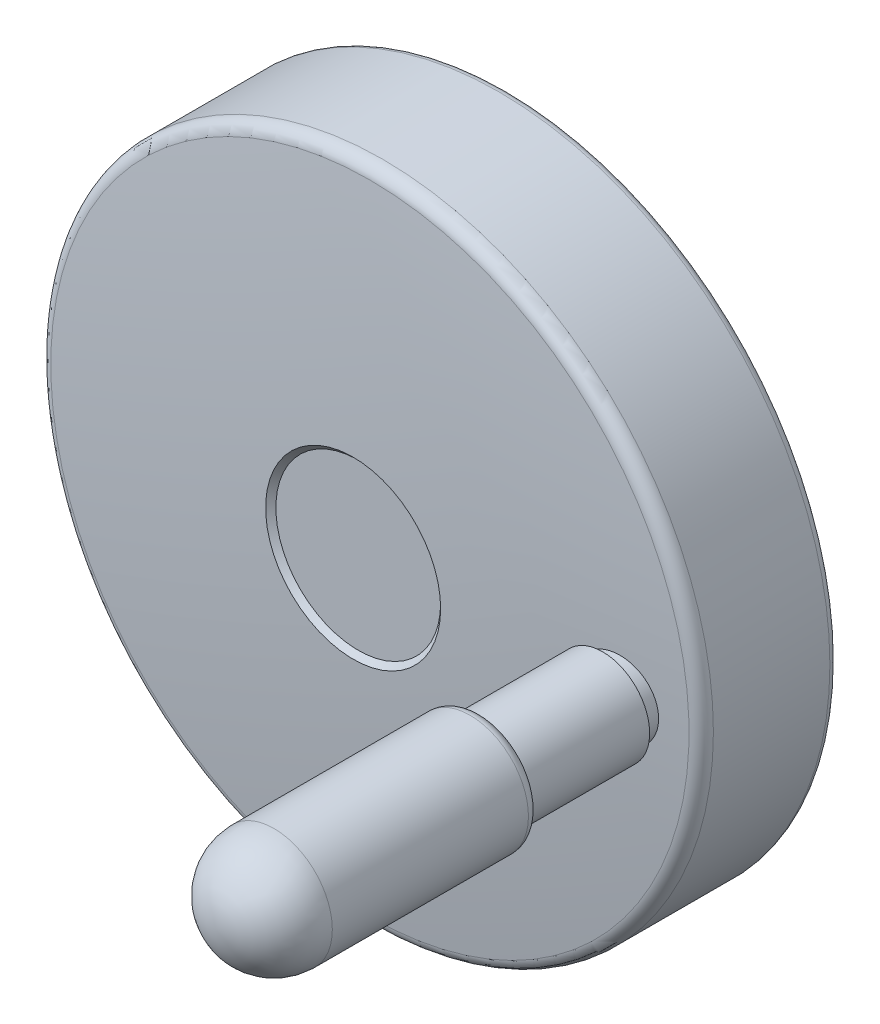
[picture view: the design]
ISO-10303-21;
HEADER;
FILE_DESCRIPTION(('STEP AP214'),'2;1');
FILE_NAME('part.step','',(''),(''),'','','');
FILE_SCHEMA(('AUTOMOTIVE_DESIGN { 1 0 10303 214 1 1 1 1 }'));
ENDSEC;
DATA;
#1=APPLICATION_CONTEXT('core data for automotive mechanical design processes');
#2=APPLICATION_PROTOCOL_DEFINITION('international standard','automotive_design',2000,#1);
#3=PRODUCT_CONTEXT('',#1,'mechanical');
#4=PRODUCT('Part','Part','',(#3));
#5=PRODUCT_RELATED_PRODUCT_CATEGORY('part','',(#4));
#6=PRODUCT_DEFINITION_FORMATION('','',#4);
#7=PRODUCT_DEFINITION_CONTEXT('part definition',#1,'design');
#8=PRODUCT_DEFINITION('design','',#6,#7);
#9=PRODUCT_DEFINITION_SHAPE('','',#8);
#10=(LENGTH_UNIT() NAMED_UNIT(*) SI_UNIT(.MILLI.,.METRE.));
#11=(NAMED_UNIT(*) PLANE_ANGLE_UNIT() SI_UNIT($,.RADIAN.));
#12=(NAMED_UNIT(*) SI_UNIT($,.STERADIAN.) SOLID_ANGLE_UNIT());
#13=UNCERTAINTY_MEASURE_WITH_UNIT(LENGTH_MEASURE(1.E-05),#10,'distance_accuracy_value','');
#14=(GEOMETRIC_REPRESENTATION_CONTEXT(3) GLOBAL_UNCERTAINTY_ASSIGNED_CONTEXT((#13)) GLOBAL_UNIT_ASSIGNED_CONTEXT((#10,
#11,#12)) REPRESENTATION_CONTEXT('',''));
#15=CARTESIAN_POINT('',(0.,0.,0.));
#16=DIRECTION('',(0.,0.,1.));
#17=DIRECTION('',(1.,0.,0.));
#18=AXIS2_PLACEMENT_3D('',#15,#16,#17);
#19=CARTESIAN_POINT('',(0.,0.,34.));
#20=DIRECTION('',(0.,0.,1.));
#21=DIRECTION('',(0.,1.,0.));
#22=AXIS2_PLACEMENT_3D('',#19,#20,#21);
#23=PLANE('',#22);
#24=CARTESIAN_POINT('',(39.,0.,34.));
#25=DIRECTION('',(0.,0.,1.));
#26=DIRECTION('',(0.,1.,0.));
#27=AXIS2_PLACEMENT_3D('',#24,#25,#26);
#28=CIRCLE('',#27,5.4375);
#29=CARTESIAN_POINT('',(39.,5.43749999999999,34.));
#30=VERTEX_POINT('',#29);
#31=EDGE_CURVE('E392',#30,#30,#28,.T.);
#32=ORIENTED_EDGE('',*,*,#31,.F.);
#33=EDGE_LOOP('',(#32));
#34=FACE_BOUND('',#33,.T.);
#35=CARTESIAN_POINT('',(39.,0.,34.));
#36=DIRECTION('',(0.,0.,-1.));
#37=DIRECTION('',(0.,-1.,0.));
#38=AXIS2_PLACEMENT_3D('',#35,#36,#37);
#39=CIRCLE('',#38,6.);
#40=CARTESIAN_POINT('',(39.,-6.,34.));
#41=VERTEX_POINT('',#40);
#42=EDGE_CURVE('E433',#41,#41,#39,.T.);
#43=ORIENTED_EDGE('',*,*,#42,.F.);
#44=EDGE_LOOP('',(#43));
#45=FACE_BOUND('',#44,.T.);
#46=ADVANCED_FACE('F15',(#34,#45),#23,.T.);
#47=CARTESIAN_POINT('',(39.,0.,31.));
#48=DIRECTION('',(0.,0.,-1.));
#49=DIRECTION('',(0.,-1.,0.));
#50=AXIS2_PLACEMENT_3D('',#47,#48,#49);
#51=CYLINDRICAL_SURFACE('',#50,6.);
#52=CARTESIAN_POINT('',(33.,0.,32.74646972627));
#53=CARTESIAN_POINT('',(33.0000009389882,0.167957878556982,32.746469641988));
#54=CARTESIAN_POINT('',(33.0070584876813,0.335946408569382,32.7458350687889));
#55=CARTESIAN_POINT('',(33.0352437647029,0.67076337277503,32.7433007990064));
#56=CARTESIAN_POINT('',(33.0563756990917,0.837591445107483,32.7414007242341));
#57=CARTESIAN_POINT('',(33.1126039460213,1.16913659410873,32.7363449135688));
#58=CARTESIAN_POINT('',(33.1477224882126,1.3338498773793,32.7331871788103));
#59=CARTESIAN_POINT('',(33.2317016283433,1.65984619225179,32.7256359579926));
#60=CARTESIAN_POINT('',(33.2805732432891,1.82112636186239,32.7212414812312));
#61=CARTESIAN_POINT('',(33.3915896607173,2.13868510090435,32.7112588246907));
#62=CARTESIAN_POINT('',(33.4537102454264,2.29497220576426,32.7056728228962));
#63=CARTESIAN_POINT('',(33.5908580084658,2.60181401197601,32.6933399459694));
#64=CARTESIAN_POINT('',(33.6658910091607,2.75236608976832,32.6865925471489));
#65=CARTESIAN_POINT('',(33.8283063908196,3.04660896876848,32.67198682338));
#66=CARTESIAN_POINT('',(33.9156894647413,3.19029938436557,32.6641284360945));
#67=CARTESIAN_POINT('',(34.1021303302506,3.4697365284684,32.6473612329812));
#68=CARTESIAN_POINT('',(34.2011828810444,3.60548678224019,32.6384528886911));
#69=CARTESIAN_POINT('',(34.4105368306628,3.868480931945,32.6196238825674));
#70=CARTESIAN_POINT('',(34.5208648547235,3.99570346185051,32.6097008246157));
#71=CARTESIAN_POINT('',(34.7516660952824,4.24027152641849,32.5889414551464));
#72=CARTESIAN_POINT('',(34.8721294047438,4.35762648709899,32.5781060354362));
#73=CARTESIAN_POINT('',(35.1224921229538,4.58183185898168,32.5555855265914));
#74=CARTESIAN_POINT('',(35.2523959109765,4.68867734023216,32.5439000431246));
#75=CARTESIAN_POINT('',(35.5206970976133,4.89108337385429,32.5197639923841));
#76=CARTESIAN_POINT('',(35.6590964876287,4.98664126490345,32.5073132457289));
#77=CARTESIAN_POINT('',(35.9438733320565,5.16609261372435,32.4816928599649));
#78=CARTESIAN_POINT('',(36.0902767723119,5.24994450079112,32.4685208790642));
#79=CARTESIAN_POINT('',(36.3896344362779,5.40503648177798,32.4415862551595));
#80=CARTESIAN_POINT('',(36.5425910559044,5.47627191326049,32.4278233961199));
#81=CARTESIAN_POINT('',(36.8538629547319,5.60557650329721,32.3998141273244));
#82=CARTESIAN_POINT('',(37.0121762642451,5.66365044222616,32.3855678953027));
#83=CARTESIAN_POINT('',(37.3331552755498,5.7662838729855,32.3566823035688));
#84=CARTESIAN_POINT('',(37.4958225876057,5.8108382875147,32.342042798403));
#85=CARTESIAN_POINT('',(37.8248270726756,5.88621612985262,32.3124319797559));
#86=CARTESIAN_POINT('',(37.9911742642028,5.9169954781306,32.2974597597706));
#87=CARTESIAN_POINT('',(38.3259327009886,5.96441315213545,32.2673279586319));
#88=CARTESIAN_POINT('',(38.4943448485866,5.98104505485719,32.2521682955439));
#89=CARTESIAN_POINT('',(38.8319675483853,6.00002939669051,32.2217754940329));
#90=CARTESIAN_POINT('',(39.00117811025,6.00238166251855,32.2065423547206));
#91=CARTESIAN_POINT('',(39.3391201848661,5.99279224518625,32.1761175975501));
#92=CARTESIAN_POINT('',(39.5078518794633,5.9808570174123,32.1609259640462));
#93=CARTESIAN_POINT('',(39.8440908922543,5.94274356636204,32.1306513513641));
#94=CARTESIAN_POINT('',(40.0115946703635,5.91653385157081,32.1155686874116));
#95=CARTESIAN_POINT('',(40.343743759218,5.85004512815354,32.0856592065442));
#96=CARTESIAN_POINT('',(40.5083901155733,5.80977138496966,32.0708322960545));
#97=CARTESIAN_POINT('',(40.833778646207,5.7154144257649,32.0415285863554));
#98=CARTESIAN_POINT('',(40.9945192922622,5.66132589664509,32.0270519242));
#99=CARTESIAN_POINT('',(41.3108232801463,5.53974661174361,31.9985634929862));
#100=CARTESIAN_POINT('',(41.4663885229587,5.47226084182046,31.9845515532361));
#101=CARTESIAN_POINT('',(41.7712243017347,5.3243780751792,31.9570933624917));
#102=CARTESIAN_POINT('',(41.9204975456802,5.24398670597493,31.9436468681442));
#103=CARTESIAN_POINT('',(42.2117156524,5.07085509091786,31.9174128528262));
#104=CARTESIAN_POINT('',(42.3536622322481,4.97811775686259,31.9046251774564));
#105=CARTESIAN_POINT('',(42.6291782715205,4.7809774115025,31.8798034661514));
#106=CARTESIAN_POINT('',(42.7627516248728,4.67657988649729,31.8677690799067));
#107=CARTESIAN_POINT('',(43.0207558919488,4.45671145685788,31.8445230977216));
#108=CARTESIAN_POINT('',(43.1451777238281,4.34122980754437,31.833312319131));
#109=CARTESIAN_POINT('',(43.3833915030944,4.10054176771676,31.8118477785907));
#110=CARTESIAN_POINT('',(43.497220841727,3.97537268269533,31.8015906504));
#111=CARTESIAN_POINT('',(43.7139888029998,3.71576617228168,31.7820571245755));
#112=CARTESIAN_POINT('',(43.8169224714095,3.58132457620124,31.7727811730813));
#113=CARTESIAN_POINT('',(44.0110846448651,3.30418746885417,31.7552835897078));
#114=CARTESIAN_POINT('',(44.1023139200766,3.1614925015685,31.7470618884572));
#115=CARTESIAN_POINT('',(44.2723701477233,2.86892460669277,31.7317358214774));
#116=CARTESIAN_POINT('',(44.3512027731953,2.71905500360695,31.7246309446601));
#117=CARTESIAN_POINT('',(44.495778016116,2.41348899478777,31.7116006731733));
#118=CARTESIAN_POINT('',(44.5615493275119,2.25780627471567,31.7056726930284));
#119=CARTESIAN_POINT('',(44.6796916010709,1.94153919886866,31.6950243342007));
#120=CARTESIAN_POINT('',(44.7320733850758,1.78095891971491,31.6903029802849));
#121=CARTESIAN_POINT('',(44.8230489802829,1.4561921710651,31.6821029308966));
#122=CARTESIAN_POINT('',(44.8616649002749,1.29201193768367,31.6786222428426));
#123=CARTESIAN_POINT('',(44.924935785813,0.960995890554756,31.6729192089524));
#124=CARTESIAN_POINT('',(44.9495949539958,0.794160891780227,31.6706964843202));
#125=CARTESIAN_POINT('',(44.9781180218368,0.522551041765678,31.6681254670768));
#126=CARTESIAN_POINT('',(44.9863211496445,0.418216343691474,31.6673860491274));
#127=CARTESIAN_POINT('',(44.9972624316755,0.209258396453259,31.6663998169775));
#128=CARTESIAN_POINT('',(45.000000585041,0.104635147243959,31.6661530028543));
#129=CARTESIAN_POINT('',(44.999999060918,-0.167955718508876,31.6661531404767));
#130=CARTESIAN_POINT('',(44.9929416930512,-0.335942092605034,31.6667892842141));
#131=CARTESIAN_POINT('',(44.9647571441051,-0.670754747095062,31.6693297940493));
#132=CARTESIAN_POINT('',(44.9436257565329,-0.837580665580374,31.6712345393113));
#133=CARTESIAN_POINT('',(44.8873989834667,-1.16912152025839,31.6763026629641));
#134=CARTESIAN_POINT('',(44.8522813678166,-1.33383266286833,31.6794680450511));
#135=CARTESIAN_POINT('',(44.7683044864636,-1.65982470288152,31.6870373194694));
#136=CARTESIAN_POINT('',(44.7194342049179,-1.82110273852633,31.6914422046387));
#137=CARTESIAN_POINT('',(44.6084209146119,-2.13865716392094,31.7014481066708));
#138=CARTESIAN_POINT('',(44.5463021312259,-2.29494209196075,31.7070469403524));
#139=CARTESIAN_POINT('',(44.4091584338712,-2.60177964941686,31.7194075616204));
#140=CARTESIAN_POINT('',(44.3341276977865,-2.75232965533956,31.7261698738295));
#141=CARTESIAN_POINT('',(44.1717173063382,-3.04656858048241,31.7408070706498));
#142=CARTESIAN_POINT('',(44.0843369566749,-3.19025711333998,31.7486820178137));
#143=CARTESIAN_POINT('',(43.8979019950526,-3.46969074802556,31.7654835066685));
#144=CARTESIAN_POINT('',(43.7988526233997,-3.60543937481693,31.7744095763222));
#145=CARTESIAN_POINT('',(43.5895042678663,-3.86843211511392,31.7932748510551));
#146=CARTESIAN_POINT('',(43.4791785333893,-3.99565476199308,31.8032164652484));
#147=CARTESIAN_POINT('',(43.2483820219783,-4.24022325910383,31.8240130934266));
#148=CARTESIAN_POINT('',(43.127921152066,-4.3575785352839,31.8348672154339));
#149=CARTESIAN_POINT('',(42.8775634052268,-4.58178480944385,31.8574247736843));
#150=CARTESIAN_POINT('',(42.7476621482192,-4.68863087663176,31.8691286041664));
#151=CARTESIAN_POINT('',(42.4793660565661,-4.89103839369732,31.8933004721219));
#152=CARTESIAN_POINT('',(42.3409692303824,-4.98659718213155,31.9057686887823));
#153=CARTESIAN_POINT('',(42.0561950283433,-5.16605221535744,31.9314229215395));
#154=CARTESIAN_POINT('',(41.9097915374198,-5.24990668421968,31.9446112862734));
#155=CARTESIAN_POINT('',(41.6104334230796,-5.40500375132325,31.9715768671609));
#156=CARTESIAN_POINT('',(41.457476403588,-5.47624168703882,31.9853542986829));
#157=CARTESIAN_POINT('',(41.1462033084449,-5.6055511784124,32.0133904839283));
#158=CARTESIAN_POINT('',(40.9878892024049,-5.66362751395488,32.0276490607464));
#159=CARTESIAN_POINT('',(40.6669081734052,-5.76626558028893,32.0565567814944));
#160=CARTESIAN_POINT('',(40.5042396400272,-5.81082223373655,32.0712060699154));
#161=CARTESIAN_POINT('',(40.175231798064,-5.88620444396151,32.1008336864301));
#162=CARTESIAN_POINT('',(40.0088824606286,-5.91698588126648,32.1158129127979));
#163=CARTESIAN_POINT('',(39.6741192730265,-5.96440735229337,32.1459556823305));
#164=CARTESIAN_POINT('',(39.505704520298,-5.98104096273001,32.1611193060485));
#165=CARTESIAN_POINT('',(39.1680761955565,-6.00002825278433,32.1915168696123));
#166=CARTESIAN_POINT('',(38.9988626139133,-6.00238175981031,32.2067508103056));
#167=CARTESIAN_POINT('',(38.6609141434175,-5.99279427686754,32.2371739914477));
#168=CARTESIAN_POINT('',(38.4921790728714,-5.98085974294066,32.2523632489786));
#169=CARTESIAN_POINT('',(38.1559354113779,-5.94274733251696,32.2826297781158));
#170=CARTESIAN_POINT('',(37.9884303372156,-5.91653816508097,32.2977067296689));
#171=CARTESIAN_POINT('',(37.656278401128,-5.85005025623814,32.3276018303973));
#172=CARTESIAN_POINT('',(37.4916304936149,-5.80977678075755,32.3424200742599));
#173=CARTESIAN_POINT('',(37.1662386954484,-5.71542003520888,32.3717037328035));
#174=CARTESIAN_POINT('',(37.0054963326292,-5.66133145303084,32.3861690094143));
#175=CARTESIAN_POINT('',(36.6891888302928,-5.53975171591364,32.414632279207));
#176=CARTESIAN_POINT('',(36.5336217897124,-5.47226554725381,32.4286304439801));
#177=CARTESIAN_POINT('',(36.2287851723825,-5.32438296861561,32.4560588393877));
#178=CARTESIAN_POINT('',(36.0795127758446,-5.24399241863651,32.4694893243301));
#179=CARTESIAN_POINT('',(35.7882961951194,-5.07086255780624,32.4956897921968));
#180=CARTESIAN_POINT('',(35.6463502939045,-4.97812615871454,32.5084599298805));
#181=CARTESIAN_POINT('',(35.3708354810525,-4.78098781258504,32.5332455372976));
#182=CARTESIAN_POINT('',(35.2372626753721,-4.67659135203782,32.5452613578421));
#183=CARTESIAN_POINT('',(34.9792593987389,-4.45672520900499,32.5684696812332));
#184=CARTESIAN_POINT('',(34.8548380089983,-4.34124478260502,32.5796613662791));
#185=CARTESIAN_POINT('',(34.6166255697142,-4.10055993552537,32.6010877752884));
#186=CARTESIAN_POINT('',(34.5027970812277,-3.97539286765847,32.6113258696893));
#187=CARTESIAN_POINT('',(34.2860305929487,-3.7157906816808,32.6308219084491));
#188=CARTESIAN_POINT('',(34.1830975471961,-3.58135139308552,32.6400794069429));
#189=CARTESIAN_POINT('',(33.9889363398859,-3.30421917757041,32.6575412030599));
#190=CARTESIAN_POINT('',(33.8977074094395,-3.1615267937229,32.6657455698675));
#191=CARTESIAN_POINT('',(33.7276515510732,-2.86896433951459,32.6810385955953));
#192=CARTESIAN_POINT('',(33.6488189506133,-2.71909759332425,32.6881277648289));
#193=CARTESIAN_POINT('',(33.504242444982,-2.41353555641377,32.7011288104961));
#194=CARTESIAN_POINT('',(33.4384700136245,-2.25785387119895,32.7070432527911));
#195=CARTESIAN_POINT('',(33.3203254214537,-1.94158894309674,32.7176669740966));
#196=CARTESIAN_POINT('',(33.2679424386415,-1.78100977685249,32.7223772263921));
#197=CARTESIAN_POINT('',(33.1769643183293,-1.45624526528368,32.7305578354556));
#198=CARTESIAN_POINT('',(33.1383470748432,-1.2920661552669,32.7340301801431));
#199=CARTESIAN_POINT('',(33.0750733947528,-0.961052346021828,32.7397195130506));
#200=CARTESIAN_POINT('',(33.050412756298,-0.794218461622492,32.7419368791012));
#201=CARTESIAN_POINT('',(33.0218860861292,-0.522600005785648,32.7445018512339));
#202=CARTESIAN_POINT('',(33.0136814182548,-0.418255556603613,32.7452395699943));
#203=CARTESIAN_POINT('',(33.0027380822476,-0.209278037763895,32.7462235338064));
#204=CARTESIAN_POINT('',(32.99999941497,-0.10464496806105,32.7464697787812));
#205=CARTESIAN_POINT('',(33.,0.,32.74646972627));
#206=B_SPLINE_CURVE_WITH_KNOTS('',3,(#52,#53,#54,#55,#56,#57,#58,#59,#60,#61,#62,#63,#64,#65,
#66,#67,#68,#69,#70,#71,#72,#73,#74,#75,#76,#77,#78,#79,#80,#81,#82,#83,#84,#85,#86,#87,#88,#89,
#90,#91,#92,#93,#94,#95,#96,#97,#98,#99,#100,#101,#102,#103,#104,#105,#106,#107,#108,#109,#110,
#111,#112,#113,#114,#115,#116,#117,#118,#119,#120,#121,#122,#123,#124,#125,#126,#127,#128,#129,
#130,#131,#132,#133,#134,#135,#136,#137,#138,#139,#140,#141,#142,#143,#144,#145,#146,#147,#148,
#149,#150,#151,#152,#153,#154,#155,#156,#157,#158,#159,#160,#161,#162,#163,#164,#165,#166,#167,
#168,#169,#170,#171,#172,#173,#174,#175,#176,#177,#178,#179,#180,#181,#182,#183,#184,#185,#186,
#187,#188,#189,#190,#191,#192,#193,#194,#195,#196,#197,#198,#199,#200,#201,#202,#203,#204,#205),
.UNSPECIFIED.,.T.,.F.,(4,2,2,2,2,2,2,2,2,2,2,2,2,2,2,2,2,2,2,2,2,2,2,2,2,2,2,2,2,2,2,2,2,2,2,2,
2,2,2,2,2,2,2,2,2,2,2,2,2,2,2,2,2,2,2,2,2,2,2,2,2,2,2,2,2,2,2,2,2,2,2,2,2,2,2,2,4),(0.,
0.503777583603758,1.00770578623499,1.51243812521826,2.01757594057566,2.52179820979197,
3.02624843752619,3.53072698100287,4.03497981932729,4.54045215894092,5.04543602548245,
5.55065565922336,6.05599417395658,6.56308393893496,7.07036071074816,7.57745293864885,
8.0847353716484,8.59362967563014,9.10275489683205,9.61188629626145,10.1207877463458,
10.6308164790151,11.1406544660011,11.6506888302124,12.1605337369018,12.6701569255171,
13.1796601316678,13.6889246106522,14.1986878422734,14.7065773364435,15.2146967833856,
15.722782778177,16.2306355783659,16.7373600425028,17.2436736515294,17.7491703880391,
18.2545148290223,18.5683603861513,18.8822059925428,19.3859771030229,19.8898988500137,
20.3946247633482,20.8997561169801,21.4039716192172,21.908415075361,22.4128869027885,
22.9171330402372,23.4226044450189,23.9275873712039,24.4328061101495,24.9381437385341,
25.4452412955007,25.9525258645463,26.4596259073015,26.9669161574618,27.4758197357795,
27.9849542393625,28.494094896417,29.0030055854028,29.5130363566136,30.0228763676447,
30.5329127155,31.0427595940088,31.5523755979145,32.0618716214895,32.5711289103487,
33.08088491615,33.5887647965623,34.0968746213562,34.6049510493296,35.1127943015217,
35.619515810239,36.1258264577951,36.6313203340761,37.1366619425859,37.450536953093,
37.7644120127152),.UNSPECIFIED.);
#207=CARTESIAN_POINT('',(33.,0.,32.74646972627));
#208=VERTEX_POINT('',#207);
#209=EDGE_CURVE('E396',#208,#208,#206,.T.);
#210=ORIENTED_EDGE('',*,*,#209,.F.);
#211=EDGE_LOOP('',(#210));
#212=FACE_BOUND('',#211,.T.);
#213=ORIENTED_EDGE('',*,*,#42,.T.);
#214=EDGE_LOOP('',(#213));
#215=FACE_BOUND('',#214,.T.);
#216=ADVANCED_FACE('F407',(#212,#215),#51,.T.);
#217=CARTESIAN_POINT('',(2.81085775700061E-13,0.,-401.000000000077));
#218=DIRECTION('',(-1.,0.,0.));
#219=DIRECTION('',(0.,0.,1.));
#220=AXIS2_PLACEMENT_3D('',#217,#218,#219);
#221=SPHERICAL_SURFACE('',#220,435.000000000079);
#222=CARTESIAN_POINT('',(0.,0.,31.2057017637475));
#223=DIRECTION('',(0.,0.,1.));
#224=DIRECTION('',(0.,1.,0.));
#225=AXIS2_PLACEMENT_3D('',#222,#223,#224);
#226=CIRCLE('',#225,49.2263279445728);
#227=CARTESIAN_POINT('',(0.,49.2263279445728,31.2057017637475));
#228=VERTEX_POINT('',#227);
#229=EDGE_CURVE('E389',#228,#228,#226,.T.);
#230=ORIENTED_EDGE('',*,*,#229,.T.);
#231=EDGE_LOOP('',(#230));
#232=FACE_BOUND('',#231,.T.);
#233=CARTESIAN_POINT('',(0.,0.,33.7904667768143));
#234=DIRECTION('',(0.,0.,1.));
#235=DIRECTION('',(1.,0.,0.));
#236=AXIS2_PLACEMENT_3D('',#233,#234,#235);
#237=CIRCLE('',#236,13.5);
#238=CARTESIAN_POINT('',(13.5,0.,33.7904667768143));
#239=VERTEX_POINT('',#238);
#240=EDGE_CURVE('E393',#239,#239,#237,.F.);
#241=ORIENTED_EDGE('',*,*,#240,.T.);
#242=EDGE_LOOP('',(#241));
#243=FACE_BOUND('',#242,.T.);
#244=ORIENTED_EDGE('',*,*,#209,.T.);
#245=EDGE_LOOP('',(#244));
#246=FACE_BOUND('',#245,.T.);
#247=ADVANCED_FACE('F411',(#232,#243,#246),#221,.T.);
#248=CARTESIAN_POINT('',(0.,0.,29.21854911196));
#249=DIRECTION('',(0.,0.,1.));
#250=DIRECTION('',(0.,1.,0.));
#251=AXIS2_PLACEMENT_3D('',#248,#249,#250);
#252=TOROIDAL_SURFACE('',#251,49.,2.00000000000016);
#253=CARTESIAN_POINT('',(0.,0.,29.21854911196));
#254=DIRECTION('',(0.,0.,1.));
#255=DIRECTION('',(0.,1.,0.));
#256=AXIS2_PLACEMENT_3D('',#253,#254,#255);
#257=CIRCLE('',#256,51.);
#258=CARTESIAN_POINT('',(0.,51.,29.21854911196));
#259=VERTEX_POINT('',#258);
#260=EDGE_CURVE('E404',#259,#259,#257,.T.);
#261=ORIENTED_EDGE('',*,*,#260,.T.);
#262=EDGE_LOOP('',(#261));
#263=FACE_BOUND('',#262,.T.);
#264=ORIENTED_EDGE('',*,*,#229,.F.);
#265=EDGE_LOOP('',(#264));
#266=FACE_BOUND('',#265,.T.);
#267=ADVANCED_FACE('F417',(#263,#266),#252,.T.);
#268=CARTESIAN_POINT('',(0.,0.,33.7904667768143));
#269=DIRECTION('',(0.,0.,1.));
#270=DIRECTION('',(1.,0.,0.));
#271=AXIS2_PLACEMENT_3D('',#268,#269,#270);
#272=CONICAL_SURFACE('',#271,13.5,0.78539816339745);
#273=CARTESIAN_POINT('',(0.,0.,33.));
#274=DIRECTION('',(0.,0.,1.));
#275=DIRECTION('',(1.,0.,0.));
#276=AXIS2_PLACEMENT_3D('',#273,#274,#275);
#277=CIRCLE('',#276,12.7095332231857);
#278=CARTESIAN_POINT('',(12.7095332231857,0.,33.));
#279=VERTEX_POINT('',#278);
#280=EDGE_CURVE('E405',#279,#279,#277,.T.);
#281=ORIENTED_EDGE('',*,*,#280,.F.);
#282=EDGE_LOOP('',(#281));
#283=FACE_BOUND('',#282,.T.);
#284=ORIENTED_EDGE('',*,*,#240,.F.);
#285=EDGE_LOOP('',(#284));
#286=FACE_BOUND('',#285,.T.);
#287=ADVANCED_FACE('F859',(#283,#286),#272,.F.);
#288=CARTESIAN_POINT('',(0.,0.,20.2342745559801));
#289=DIRECTION('',(0.,0.,-1.));
#290=DIRECTION('',(-1.,0.,0.));
#291=AXIS2_PLACEMENT_3D('',#288,#289,#290);
#292=CYLINDRICAL_SURFACE('',#291,51.);
#293=CARTESIAN_POINT('',(0.,0.,11.25));
#294=DIRECTION('',(0.,0.,-1.));
#295=DIRECTION('',(-1.,0.,0.));
#296=AXIS2_PLACEMENT_3D('',#293,#294,#295);
#297=CIRCLE('',#296,51.);
#298=CARTESIAN_POINT('',(-51.,0.,11.25));
#299=VERTEX_POINT('',#298);
#300=EDGE_CURVE('E273',#299,#299,#297,.F.);
#301=ORIENTED_EDGE('',*,*,#300,.T.);
#302=EDGE_LOOP('',(#301));
#303=FACE_BOUND('',#302,.T.);
#304=ORIENTED_EDGE('',*,*,#260,.F.);
#305=EDGE_LOOP('',(#304));
#306=FACE_BOUND('',#305,.T.);
#307=ADVANCED_FACE('F867',(#303,#306),#292,.T.);
#308=CARTESIAN_POINT('',(-6.35476661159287,0.,33.));
#309=DIRECTION('',(0.,0.,1.));
#310=DIRECTION('',(0.,1.,0.));
#311=AXIS2_PLACEMENT_3D('',#308,#309,#310);
#312=PLANE('',#311);
#313=ORIENTED_EDGE('',*,*,#280,.T.);
#314=EDGE_LOOP('',(#313));
#315=FACE_BOUND('',#314,.T.);
#316=ADVANCED_FACE('F262',(#315),#312,.T.);
#317=CARTESIAN_POINT('',(0.,0.,11.25));
#318=DIRECTION('',(0.,0.,1.));
#319=DIRECTION('',(0.,1.,0.));
#320=AXIS2_PLACEMENT_3D('',#317,#318,#319);
#321=TOROIDAL_SURFACE('',#320,49.75,1.25);
#322=ORIENTED_EDGE('',*,*,#300,.F.);
#323=EDGE_LOOP('',(#322));
#324=FACE_BOUND('',#323,.T.);
#325=CARTESIAN_POINT('',(0.,0.,10.));
#326=DIRECTION('',(0.,0.,1.));
#327=DIRECTION('',(0.,-1.,0.));
#328=AXIS2_PLACEMENT_3D('',#325,#326,#327);
#329=CIRCLE('',#328,49.75);
#330=CARTESIAN_POINT('',(0.,-49.75,10.));
#331=VERTEX_POINT('',#330);
#332=CARTESIAN_POINT('',(0.,49.75,10.));
#333=VERTEX_POINT('',#332);
#334=EDGE_CURVE('E304',#331,#333,#329,.T.);
#335=ORIENTED_EDGE('',*,*,#334,.T.);
#336=CARTESIAN_POINT('',(0.,0.,10.));
#337=DIRECTION('',(0.,0.,1.));
#338=DIRECTION('',(0.,1.,0.));
#339=AXIS2_PLACEMENT_3D('',#336,#337,#338);
#340=CIRCLE('',#339,49.75);
#341=CARTESIAN_POINT('',(-49.75,0.,10.));
#342=VERTEX_POINT('',#341);
#343=EDGE_CURVE('E245',#333,#342,#340,.T.);
#344=ORIENTED_EDGE('',*,*,#343,.T.);
#345=CARTESIAN_POINT('',(0.,0.,10.));
#346=DIRECTION('',(0.,0.,1.));
#347=DIRECTION('',(-1.,0.,0.));
#348=AXIS2_PLACEMENT_3D('',#345,#346,#347);
#349=CIRCLE('',#348,49.75);
#350=EDGE_CURVE('E38',#342,#331,#349,.T.);
#351=ORIENTED_EDGE('',*,*,#350,.T.);
#352=EDGE_LOOP('',(#335,#344,#351));
#353=FACE_BOUND('',#352,.T.);
#354=ADVANCED_FACE('F250',(#324,#353),#321,.T.);
#355=CARTESIAN_POINT('',(-49.355,0.,10.));
#356=DIRECTION('',(0.,0.,-1.));
#357=DIRECTION('',(-1.,0.,0.));
#358=AXIS2_PLACEMENT_3D('',#355,#356,#357);
#359=PLANE('',#358);
#360=CARTESIAN_POINT('',(0.,0.,10.));
#361=DIRECTION('',(0.,0.,-1.));
#362=DIRECTION('',(-1.,0.,0.));
#363=AXIS2_PLACEMENT_3D('',#360,#361,#362);
#364=CIRCLE('',#363,48.96);
#365=CARTESIAN_POINT('',(-48.96,0.,9.99999999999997));
#366=VERTEX_POINT('',#365);
#367=EDGE_CURVE('E324',#366,#366,#364,.F.);
#368=ORIENTED_EDGE('',*,*,#367,.T.);
#369=EDGE_LOOP('',(#368));
#370=FACE_BOUND('',#369,.T.);
#371=ORIENTED_EDGE('',*,*,#343,.F.);
#372=ORIENTED_EDGE('',*,*,#334,.F.);
#373=ORIENTED_EDGE('',*,*,#350,.F.);
#374=EDGE_LOOP('',(#371,#372,#373));
#375=FACE_BOUND('',#374,.T.);
#376=ADVANCED_FACE('F261',(#370,#375),#359,.T.);
#377=CARTESIAN_POINT('',(0.,0.,11.8));
#378=DIRECTION('',(0.,0.,-1.));
#379=DIRECTION('',(-1.,0.,0.));
#380=AXIS2_PLACEMENT_3D('',#377,#378,#379);
#381=CYLINDRICAL_SURFACE('',#380,48.96);
#382=ORIENTED_EDGE('',*,*,#367,.F.);
#383=EDGE_LOOP('',(#382));
#384=FACE_BOUND('',#383,.T.);
#385=CARTESIAN_POINT('',(0.,0.,13.6));
#386=DIRECTION('',(0.,0.,-1.));
#387=DIRECTION('',(-1.,0.,0.));
#388=AXIS2_PLACEMENT_3D('',#385,#386,#387);
#389=CIRCLE('',#388,48.96);
#390=CARTESIAN_POINT('',(-48.96,0.,13.6));
#391=VERTEX_POINT('',#390);
#392=EDGE_CURVE('E328',#391,#391,#389,.T.);
#393=ORIENTED_EDGE('',*,*,#392,.F.);
#394=EDGE_LOOP('',(#393));
#395=FACE_BOUND('',#394,.T.);
#396=ADVANCED_FACE('F289',(#384,#395),#381,.F.);
#397=CARTESIAN_POINT('',(39.,0.,25.5));
#398=DIRECTION('',(0.,0.,1.));
#399=DIRECTION('',(0.,1.,0.));
#400=AXIS2_PLACEMENT_3D('',#397,#398,#399);
#401=CYLINDRICAL_SURFACE('',#400,2.4585);
#402=CARTESIAN_POINT('',(39.,0.,21.0719999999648));
#403=DIRECTION('',(0.,0.,1.));
#404=DIRECTION('',(0.,1.,0.));
#405=AXIS2_PLACEMENT_3D('',#402,#403,#404);
#406=CIRCLE('',#405,2.4585);
#407=CARTESIAN_POINT('',(39.,2.45849999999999,21.0719999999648));
#408=VERTEX_POINT('',#407);
#409=EDGE_CURVE('E30',#408,#408,#406,.T.);
#410=ORIENTED_EDGE('',*,*,#409,.T.);
#411=EDGE_LOOP('',(#410));
#412=FACE_BOUND('',#411,.T.);
#413=CARTESIAN_POINT('',(39.,0.,17.5415));
#414=DIRECTION('',(0.,0.,1.));
#415=DIRECTION('',(0.,1.,0.));
#416=AXIS2_PLACEMENT_3D('',#413,#414,#415);
#417=CIRCLE('',#416,2.4585);
#418=CARTESIAN_POINT('',(39.,2.4585,17.5415));
#419=VERTEX_POINT('',#418);
#420=EDGE_CURVE('E325',#419,#419,#417,.T.);
#421=ORIENTED_EDGE('',*,*,#420,.F.);
#422=EDGE_LOOP('',(#421));
#423=FACE_BOUND('',#422,.T.);
#424=ADVANCED_FACE('F504',(#412,#423),#401,.F.);
#425=CARTESIAN_POINT('',(39.,0.,17.0000000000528));
#426=DIRECTION('',(0.,0.,-1.));
#427=DIRECTION('',(0.,-1.,0.));
#428=AXIS2_PLACEMENT_3D('',#425,#426,#427);
#429=CONICAL_SURFACE('',#428,2.99999999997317,0.785398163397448);
#430=ORIENTED_EDGE('',*,*,#420,.T.);
#431=EDGE_LOOP('',(#430));
#432=FACE_BOUND('',#431,.T.);
#433=CARTESIAN_POINT('',(39.,0.,16.9999999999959));
#434=DIRECTION('',(0.,0.,-1.));
#435=DIRECTION('',(0.,-1.,0.));
#436=AXIS2_PLACEMENT_3D('',#433,#434,#435);
#437=CIRCLE('',#436,3.00000000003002);
#438=CARTESIAN_POINT('',(39.,-3.00000000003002,16.9999999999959));
#439=VERTEX_POINT('',#438);
#440=EDGE_CURVE('E331',#439,#439,#437,.F.);
#441=ORIENTED_EDGE('',*,*,#440,.F.);
#442=EDGE_LOOP('',(#441));
#443=FACE_BOUND('',#442,.T.);
#444=ADVANCED_FACE('F497',(#432,#443),#429,.F.);
#445=CARTESIAN_POINT('',(42.3,0.,17.));
#446=DIRECTION('',(0.,0.,1.));
#447=DIRECTION('',(0.,1.,0.));
#448=AXIS2_PLACEMENT_3D('',#445,#446,#447);
#449=PLANE('',#448);
#450=ORIENTED_EDGE('',*,*,#440,.T.);
#451=EDGE_LOOP('',(#450));
#452=FACE_BOUND('',#451,.T.);
#453=CARTESIAN_POINT('',(39.,0.,17.));
#454=DIRECTION('',(0.,0.,1.));
#455=DIRECTION('',(0.,1.,0.));
#456=AXIS2_PLACEMENT_3D('',#453,#454,#455);
#457=CIRCLE('',#456,3.6);
#458=CARTESIAN_POINT('',(39.,3.6,17.));
#459=VERTEX_POINT('',#458);
#460=EDGE_CURVE('E335',#459,#459,#457,.T.);
#461=ORIENTED_EDGE('',*,*,#460,.F.);
#462=EDGE_LOOP('',(#461));
#463=FACE_BOUND('',#462,.T.);
#464=ADVANCED_FACE('F493',(#452,#463),#449,.F.);
#465=CARTESIAN_POINT('',(39.,0.,8.5));
#466=DIRECTION('',(0.,0.,1.));
#467=DIRECTION('',(0.,1.,0.));
#468=AXIS2_PLACEMENT_3D('',#465,#466,#467);
#469=CYLINDRICAL_SURFACE('',#468,3.6);
#470=CARTESIAN_POINT('',(35.6551589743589,-1.33117936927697,13.6));
#471=CARTESIAN_POINT('',(35.6298127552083,-1.26750935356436,13.6277047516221));
#472=CARTESIAN_POINT('',(35.6060345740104,-1.2024530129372,13.6537276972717));
#473=CARTESIAN_POINT('',(35.5619033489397,-1.06975467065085,13.7020707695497));
#474=CARTESIAN_POINT('',(35.5415545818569,-1.00210956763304,13.7243862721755));
#475=CARTESIAN_POINT('',(35.5046580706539,-0.8646634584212,13.7648801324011));
#476=CARTESIAN_POINT('',(35.488105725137,-0.794865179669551,13.7830634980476));
#477=CARTESIAN_POINT('',(35.4590718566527,-0.653477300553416,13.8149769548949));
#478=CARTESIAN_POINT('',(35.4465875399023,-0.581888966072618,13.8287101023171));
#479=CARTESIAN_POINT('',(35.4242827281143,-0.425901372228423,13.853255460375));
#480=CARTESIAN_POINT('',(35.4151960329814,-0.341266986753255,13.8632619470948));
#481=CARTESIAN_POINT('',(35.4030565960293,-0.171085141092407,13.8766320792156));
#482=CARTESIAN_POINT('',(35.4000006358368,-0.0855381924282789,13.879999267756));
#483=CARTESIAN_POINT('',(35.3999994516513,0.0737685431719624,13.8800006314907));
#484=CARTESIAN_POINT('',(35.4022712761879,0.147530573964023,13.8774974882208));
#485=CARTESIAN_POINT('',(35.411308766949,0.294474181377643,13.8675430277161));
#486=CARTESIAN_POINT('',(35.4180762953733,0.367655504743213,13.8600896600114));
#487=CARTESIAN_POINT('',(35.4359822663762,0.512981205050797,13.840379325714));
#488=CARTESIAN_POINT('',(35.4471299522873,0.585123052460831,13.8281122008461));
#489=CARTESIAN_POINT('',(35.4735727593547,0.727717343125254,13.7990348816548));
#490=CARTESIAN_POINT('',(35.4888686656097,0.798169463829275,13.7822238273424));
#491=CARTESIAN_POINT('',(35.5261228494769,0.948194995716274,13.741315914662));
#492=CARTESIAN_POINT('',(35.5487589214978,1.02739778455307,13.7164800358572));
#493=CARTESIAN_POINT('',(35.5986334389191,1.18207465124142,13.6618284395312));
#494=CARTESIAN_POINT('',(35.625847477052,1.25756589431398,13.6320391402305));
#495=CARTESIAN_POINT('',(35.6551589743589,1.33117936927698,13.6));
#496=B_SPLINE_CURVE_WITH_KNOTS('',3,(#470,#471,#472,#473,#474,#475,#476,#477,#478,#479,#480,
#481,#482,#483,#484,#485,#486,#487,#488,#489,#490,#491,#492,#493,#494,#495),.UNSPECIFIED.,.F.,
.F.,(4,2,2,2,2,2,2,2,2,2,2,2,4),(0.,0.221744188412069,0.443762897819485,0.665511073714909,
0.887106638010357,1.14375645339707,1.40026926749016,1.6214871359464,1.84279669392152,
2.06457580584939,2.28639692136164,2.54414214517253,2.80055440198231),.UNSPECIFIED.);
#497=CARTESIAN_POINT('',(35.655158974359,-1.3311793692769,13.6));
#498=VERTEX_POINT('',#497);
#499=CARTESIAN_POINT('',(35.655158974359,1.33117936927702,13.6));
#500=VERTEX_POINT('',#499);
#501=EDGE_CURVE('E344',#498,#500,#496,.T.);
#502=ORIENTED_EDGE('',*,*,#501,.T.);
#503=CARTESIAN_POINT('',(39.,0.,13.6));
#504=DIRECTION('',(0.,0.,1.));
#505=DIRECTION('',(0.,1.,0.));
#506=AXIS2_PLACEMENT_3D('',#503,#504,#505);
#507=CIRCLE('',#506,3.6);
#508=EDGE_CURVE('E339',#498,#500,#507,.T.);
#509=ORIENTED_EDGE('',*,*,#508,.F.);
#510=EDGE_LOOP('',(#502,#509));
#511=FACE_BOUND('',#510,.T.);
#512=ORIENTED_EDGE('',*,*,#460,.T.);
#513=EDGE_LOOP('',(#512));
#514=FACE_BOUND('',#513,.T.);
#515=ADVANCED_FACE('F464',(#511,#514),#469,.F.);
#516=CARTESIAN_POINT('',(0.,0.,13.6));
#517=DIRECTION('',(0.,0.,-1.));
#518=DIRECTION('',(-1.,0.,0.));
#519=AXIS2_PLACEMENT_3D('',#516,#517,#518);
#520=CONICAL_SURFACE('',#519,35.68,0.785398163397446);
#521=CARTESIAN_POINT('',(0.,0.,14.6));
#522=DIRECTION('',(0.,0.,-1.));
#523=DIRECTION('',(-1.,0.,0.));
#524=AXIS2_PLACEMENT_3D('',#521,#522,#523);
#525=CIRCLE('',#524,34.68);
#526=CARTESIAN_POINT('',(-34.68,0.,14.6));
#527=VERTEX_POINT('',#526);
#528=EDGE_CURVE('E340',#527,#527,#525,.T.);
#529=ORIENTED_EDGE('',*,*,#528,.F.);
#530=EDGE_LOOP('',(#529));
#531=FACE_BOUND('',#530,.T.);
#532=CARTESIAN_POINT('',(0.,0.,13.6));
#533=DIRECTION('',(0.,0.,-1.));
#534=DIRECTION('',(-1.,0.,0.));
#535=AXIS2_PLACEMENT_3D('',#532,#533,#534);
#536=CIRCLE('',#535,35.68);
#537=EDGE_CURVE('E343',#500,#498,#536,.F.);
#538=ORIENTED_EDGE('',*,*,#537,.F.);
#539=ORIENTED_EDGE('',*,*,#501,.F.);
#540=EDGE_LOOP('',(#538,#539));
#541=FACE_BOUND('',#540,.T.);
#542=ADVANCED_FACE('F468',(#531,#541),#520,.F.);
#543=CARTESIAN_POINT('',(-41.1063675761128,0.,13.6));
#544=DIRECTION('',(0.,0.,-1.));
#545=DIRECTION('',(0.,-1.,0.));
#546=AXIS2_PLACEMENT_3D('',#543,#544,#545);
#547=PLANE('',#546);
#548=CARTESIAN_POINT('',(0.,0.,13.6));
#549=DIRECTION('',(0.,0.,1.));
#550=DIRECTION('',(1.,0.,0.));
#551=AXIS2_PLACEMENT_3D('',#548,#549,#550);
#552=CIRCLE('',#551,46.5327351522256);
#553=CARTESIAN_POINT('',(46.5327351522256,0.,13.6));
#554=VERTEX_POINT('',#553);
#555=EDGE_CURVE('E452',#554,#554,#552,.T.);
#556=ORIENTED_EDGE('',*,*,#555,.F.);
#557=EDGE_LOOP('',(#556));
#558=FACE_BOUND('',#557,.T.);
#559=ORIENTED_EDGE('',*,*,#508,.T.);
#560=ORIENTED_EDGE('',*,*,#537,.T.);
#561=EDGE_LOOP('',(#559,#560));
#562=FACE_BOUND('',#561,.T.);
#563=ADVANCED_FACE('F472',(#558,#562),#547,.T.);
#564=CARTESIAN_POINT('',(0.,0.,19.0568720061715));
#565=DIRECTION('',(0.,0.,-1.));
#566=DIRECTION('',(-1.,0.,0.));
#567=AXIS2_PLACEMENT_3D('',#564,#565,#566);
#568=CYLINDRICAL_SURFACE('',#567,34.68);
#569=CARTESIAN_POINT('',(0.,0.,23.513744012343));
#570=DIRECTION('',(0.,0.,-1.));
#571=DIRECTION('',(-1.,0.,0.));
#572=AXIS2_PLACEMENT_3D('',#569,#570,#571);
#573=CIRCLE('',#572,34.68);
#574=CARTESIAN_POINT('',(-34.68,0.,23.513744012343));
#575=VERTEX_POINT('',#574);
#576=EDGE_CURVE('E345',#575,#575,#573,.T.);
#577=ORIENTED_EDGE('',*,*,#576,.F.);
#578=EDGE_LOOP('',(#577));
#579=FACE_BOUND('',#578,.T.);
#580=ORIENTED_EDGE('',*,*,#528,.T.);
#581=EDGE_LOOP('',(#580));
#582=FACE_BOUND('',#581,.T.);
#583=ADVANCED_FACE('F360',(#579,#582),#568,.F.);
#584=CARTESIAN_POINT('',(0.,0.,23.8557841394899));
#585=DIRECTION('',(0.,0.,1.));
#586=DIRECTION('',(1.,0.,0.));
#587=AXIS2_PLACEMENT_3D('',#584,#585,#586);
#588=CONICAL_SURFACE('',#587,47.43,0.0872664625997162);
#589=CARTESIAN_POINT('',(0.,0.,23.8557841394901));
#590=DIRECTION('',(0.,0.,-1.));
#591=DIRECTION('',(-1.,0.,0.));
#592=AXIS2_PLACEMENT_3D('',#589,#590,#591);
#593=CIRCLE('',#592,47.43);
#594=CARTESIAN_POINT('',(-47.43,0.,23.8557841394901));
#595=VERTEX_POINT('',#594);
#596=EDGE_CURVE('E336',#595,#595,#593,.T.);
#597=ORIENTED_EDGE('',*,*,#596,.T.);
#598=EDGE_LOOP('',(#597));
#599=FACE_BOUND('',#598,.T.);
#600=ORIENTED_EDGE('',*,*,#555,.T.);
#601=EDGE_LOOP('',(#600));
#602=FACE_BOUND('',#601,.T.);
#603=ADVANCED_FACE('F358',(#599,#602),#588,.T.);
#604=CARTESIAN_POINT('',(0.,0.,23.513744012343));
#605=DIRECTION('',(0.,0.,1.));
#606=DIRECTION('',(0.,1.,0.));
#607=AXIS2_PLACEMENT_3D('',#604,#605,#606);
#608=TOROIDAL_SURFACE('',#607,33.0133333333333,1.66666666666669);
#609=ORIENTED_EDGE('',*,*,#576,.T.);
#610=EDGE_LOOP('',(#609));
#611=FACE_BOUND('',#610,.T.);
#612=CARTESIAN_POINT('',(0.,0.,25.1550902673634));
#613=DIRECTION('',(0.,0.,1.));
#614=DIRECTION('',(0.,1.,0.));
#615=AXIS2_PLACEMENT_3D('',#612,#613,#614);
#616=CIRCLE('',#615,32.7239197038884);
#617=CARTESIAN_POINT('',(0.,32.7239197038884,25.1550902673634));
#618=VERTEX_POINT('',#617);
#619=EDGE_CURVE('E348',#618,#618,#616,.F.);
#620=ORIENTED_EDGE('',*,*,#619,.F.);
#621=EDGE_LOOP('',(#620));
#622=FACE_BOUND('',#621,.T.);
#623=ADVANCED_FACE('F353',(#611,#622),#608,.F.);
#624=CARTESIAN_POINT('',(0.,0.,23.8));
#625=DIRECTION('',(0.,0.,-1.));
#626=DIRECTION('',(-1.,0.,0.));
#627=AXIS2_PLACEMENT_3D('',#624,#625,#626);
#628=CONICAL_SURFACE('',#627,48.0676156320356,1.48352986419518);
#629=CARTESIAN_POINT('',(0.,0.,23.8));
#630=DIRECTION('',(0.,0.,-1.));
#631=DIRECTION('',(-1.,0.,0.));
#632=AXIS2_PLACEMENT_3D('',#629,#630,#631);
#633=CIRCLE('',#632,48.0676156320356);
#634=CARTESIAN_POINT('',(-48.0676156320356,0.,23.8));
#635=VERTEX_POINT('',#634);
#636=EDGE_CURVE('E332',#635,#635,#633,.T.);
#637=ORIENTED_EDGE('',*,*,#636,.T.);
#638=EDGE_LOOP('',(#637));
#639=FACE_BOUND('',#638,.T.);
#640=ORIENTED_EDGE('',*,*,#596,.F.);
#641=EDGE_LOOP('',(#640));
#642=FACE_BOUND('',#641,.T.);
#643=ADVANCED_FACE('F357',(#639,#642),#628,.F.);
#644=CARTESIAN_POINT('',(0.,0.,25.1550902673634));
#645=DIRECTION('',(0.,0.,1.));
#646=DIRECTION('',(1.,0.,0.));
#647=AXIS2_PLACEMENT_3D('',#644,#645,#646);
#648=CONICAL_SURFACE('',#647,32.7239197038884,1.39626340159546);
#649=ORIENTED_EDGE('',*,*,#619,.T.);
#650=EDGE_LOOP('',(#649));
#651=FACE_BOUND('',#650,.T.);
#652=CARTESIAN_POINT('',(0.,0.,22.1755931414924));
#653=DIRECTION('',(0.,0.,1.));
#654=DIRECTION('',(-1.,0.,0.));
#655=AXIS2_PLACEMENT_3D('',#652,#653,#654);
#656=CIRCLE('',#655,15.8263518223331);
#657=CARTESIAN_POINT('',(-15.8263518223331,0.,22.1755931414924));
#658=VERTEX_POINT('',#657);
#659=EDGE_CURVE('E375',#658,#658,#656,.T.);
#660=ORIENTED_EDGE('',*,*,#659,.T.);
#661=EDGE_LOOP('',(#660));
#662=FACE_BOUND('',#661,.T.);
#663=ADVANCED_FACE('F362',(#651,#662),#648,.T.);
#664=CARTESIAN_POINT('',(0.,0.,13.6));
#665=DIRECTION('',(0.,0.,-1.));
#666=DIRECTION('',(-1.,0.,0.));
#667=AXIS2_PLACEMENT_3D('',#664,#665,#666);
#668=CONICAL_SURFACE('',#667,48.96,0.0872664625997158);
#669=ORIENTED_EDGE('',*,*,#392,.T.);
#670=EDGE_LOOP('',(#669));
#671=FACE_BOUND('',#670,.T.);
#672=ORIENTED_EDGE('',*,*,#636,.F.);
#673=EDGE_LOOP('',(#672));
#674=FACE_BOUND('',#673,.T.);
#675=ADVANCED_FACE('F365',(#671,#674),#668,.F.);
#676=CARTESIAN_POINT('',(0.,0.,21.1907853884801));
#677=DIRECTION('',(0.,0.,1.));
#678=DIRECTION('',(0.,1.,0.));
#679=AXIS2_PLACEMENT_3D('',#676,#677,#678);
#680=TOROIDAL_SURFACE('',#679,16.,1.);
#681=ORIENTED_EDGE('',*,*,#659,.F.);
#682=EDGE_LOOP('',(#681));
#683=FACE_BOUND('',#682,.T.);
#684=CARTESIAN_POINT('',(0.,0.,21.1907853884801));
#685=DIRECTION('',(0.,0.,1.));
#686=DIRECTION('',(0.,1.,0.));
#687=AXIS2_PLACEMENT_3D('',#684,#685,#686);
#688=CIRCLE('',#687,15.);
#689=CARTESIAN_POINT('',(0.,15.,21.1907853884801));
#690=VERTEX_POINT('',#689);
#691=EDGE_CURVE('E378',#690,#690,#688,.F.);
#692=ORIENTED_EDGE('',*,*,#691,.F.);
#693=EDGE_LOOP('',(#692));
#694=FACE_BOUND('',#693,.T.);
#695=ADVANCED_FACE('F367',(#683,#694),#680,.F.);
#696=CARTESIAN_POINT('',(0.,0.,10.6953926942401));
#697=DIRECTION('',(0.,0.,-1.));
#698=DIRECTION('',(-1.,0.,0.));
#699=AXIS2_PLACEMENT_3D('',#696,#697,#698);
#700=CYLINDRICAL_SURFACE('',#699,15.);
#701=CARTESIAN_POINT('',(15.,0.,2.));
#702=CARTESIAN_POINT('',(14.9999969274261,0.166730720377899,2.00000613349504));
#703=CARTESIAN_POINT('',(14.9971915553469,0.333538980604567,2.01394652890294));
#704=CARTESIAN_POINT('',(14.986270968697,0.66244052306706,2.06929550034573));
#705=CARTESIAN_POINT('',(14.9781515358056,0.824529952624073,2.11072589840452));
#706=CARTESIAN_POINT('',(14.9575094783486,1.13919091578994,2.21972382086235));
#707=CARTESIAN_POINT('',(14.9449910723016,1.2917714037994,2.28726631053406));
#708=CARTESIAN_POINT('',(14.9169119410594,1.58342396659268,2.44649674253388));
#709=CARTESIAN_POINT('',(14.9013513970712,1.72249684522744,2.53818324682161));
#710=CARTESIAN_POINT('',(14.8686649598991,1.9850804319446,2.74441548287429));
#711=CARTESIAN_POINT('',(14.8515223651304,2.10838185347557,2.85922506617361));
#712=CARTESIAN_POINT('',(14.8177254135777,2.33411026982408,3.10787724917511));
#713=CARTESIAN_POINT('',(14.8010710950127,2.43653563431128,3.24172133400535));
#714=CARTESIAN_POINT('',(14.7699732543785,2.61849526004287,3.52614857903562));
#715=CARTESIAN_POINT('',(14.7555512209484,2.6978128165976,3.67687293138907));
#716=CARTESIAN_POINT('',(14.7307880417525,2.82991699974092,3.98984545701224));
#717=CARTESIAN_POINT('',(14.7204464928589,2.88270624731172,4.15209249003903));
#718=CARTESIAN_POINT('',(14.7051841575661,2.95957589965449,4.48125309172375));
#719=CARTESIAN_POINT('',(14.7001941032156,2.98402349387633,4.64807763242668));
#720=CARTESIAN_POINT('',(14.6959912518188,3.00465638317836,4.98352946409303));
#721=CARTESIAN_POINT('',(14.6967778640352,3.00084456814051,5.15215656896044));
#722=CARTESIAN_POINT('',(14.7039765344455,2.96536371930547,5.48374036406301));
#723=CARTESIAN_POINT('',(14.7103035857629,2.93411562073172,5.64674421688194));
#724=CARTESIAN_POINT('',(14.7277363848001,2.84531365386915,5.96514822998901));
#725=CARTESIAN_POINT('',(14.7388423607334,2.78775852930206,6.12054802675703));
#726=CARTESIAN_POINT('',(14.7646685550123,2.64757435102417,6.4205457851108));
#727=CARTESIAN_POINT('',(14.7794126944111,2.56477845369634,6.56506363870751));
#728=CARTESIAN_POINT('',(14.8108385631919,2.37658072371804,6.83831254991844));
#729=CARTESIAN_POINT('',(14.827520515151,2.2711762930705,6.96704179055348));
#730=CARTESIAN_POINT('',(14.8613106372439,2.03849980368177,7.20748820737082));
#731=CARTESIAN_POINT('',(14.8784210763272,1.91086848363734,7.31885770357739));
#732=CARTESIAN_POINT('',(14.9108654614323,1.63855507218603,7.51866153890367));
#733=CARTESIAN_POINT('',(14.9261993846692,1.49387276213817,7.60709558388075));
#734=CARTESIAN_POINT('',(14.9534007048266,1.19117816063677,7.75858252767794));
#735=CARTESIAN_POINT('',(14.9652626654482,1.0331454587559,7.82159568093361));
#736=CARTESIAN_POINT('',(14.9841422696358,0.708446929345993,7.9200814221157));
#737=CARTESIAN_POINT('',(14.9911605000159,0.541782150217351,7.9555573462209));
#738=CARTESIAN_POINT('',(14.999480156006,0.207538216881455,7.99746936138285));
#739=CARTESIAN_POINT('',(15.0008752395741,0.0400209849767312,8.00438125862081));
#740=CARTESIAN_POINT('',(14.9980515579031,-0.293774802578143,7.99025042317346));
#741=CARTESIAN_POINT('',(14.9938331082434,-0.460053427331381,7.96920926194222));
#742=CARTESIAN_POINT('',(14.9803149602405,-0.785116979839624,7.90016487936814));
#743=CARTESIAN_POINT('',(14.9710612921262,-0.943955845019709,7.85240579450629));
#744=CARTESIAN_POINT('',(14.948506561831,-1.251370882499,7.73154805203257));
#745=CARTESIAN_POINT('',(14.9352051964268,-1.39994628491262,7.65844749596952));
#746=CARTESIAN_POINT('',(14.9057973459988,-1.68462352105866,7.48795252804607));
#747=CARTESIAN_POINT('',(14.8896585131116,-1.82055038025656,7.39027165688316));
#748=CARTESIAN_POINT('',(14.8564420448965,-2.07425405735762,7.17377242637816));
#749=CARTESIAN_POINT('',(14.8393643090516,-2.1920289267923,7.05495180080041));
#750=CARTESIAN_POINT('',(14.8058791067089,-2.40792177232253,6.79737994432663));
#751=CARTESIAN_POINT('',(14.7894858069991,-2.50571310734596,6.65835276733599));
#752=CARTESIAN_POINT('',(14.7595257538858,-2.67655626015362,6.36556591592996));
#753=CARTESIAN_POINT('',(14.7459588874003,-2.74960906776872,6.21180683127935));
#754=CARTESIAN_POINT('',(14.7233022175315,-2.86845552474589,5.89469526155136));
#755=CARTESIAN_POINT('',(14.7141892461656,-2.91439049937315,5.73139747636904));
#756=CARTESIAN_POINT('',(14.7014231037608,-2.97812595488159,5.39919963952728));
#757=CARTESIAN_POINT('',(14.6977692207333,-2.99593010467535,5.23030032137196));
#758=CARTESIAN_POINT('',(14.6963744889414,-3.00276273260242,4.89497340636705));
#759=CARTESIAN_POINT('',(14.698527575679,-2.99230736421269,4.72855655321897));
#760=CARTESIAN_POINT('',(14.7082672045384,-2.94405691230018,4.39990505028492));
#761=CARTESIAN_POINT('',(14.7158537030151,-2.90626204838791,4.23767036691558));
#762=CARTESIAN_POINT('',(14.7355579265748,-2.80463570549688,3.92231686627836));
#763=CARTESIAN_POINT('',(14.7476646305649,-2.74086752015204,3.76917691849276));
#764=CARTESIAN_POINT('',(14.7750514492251,-2.58916393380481,3.47568883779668));
#765=CARTESIAN_POINT('',(14.7903318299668,-2.50122650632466,3.33534177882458));
#766=CARTESIAN_POINT('',(14.8226688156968,-2.30191774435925,3.06885328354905));
#767=CARTESIAN_POINT('',(14.839751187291,-2.19017366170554,2.94299370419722));
#768=CARTESIAN_POINT('',(14.8735824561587,-1.94719310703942,2.71164138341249));
#769=CARTESIAN_POINT('',(14.8903312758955,-1.81595216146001,2.60615332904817));
#770=CARTESIAN_POINT('',(14.9218149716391,-1.53605288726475,2.41749606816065));
#771=CARTESIAN_POINT('',(14.9365269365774,-1.38722665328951,2.33457199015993));
#772=CARTESIAN_POINT('',(14.96205375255,-1.0774990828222,2.19504163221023));
#773=CARTESIAN_POINT('',(14.9728721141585,-0.916608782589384,2.13841163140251));
#774=CARTESIAN_POINT('',(14.9872911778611,-0.629464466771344,2.06404415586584));
#775=CARTESIAN_POINT('',(14.9920290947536,-0.504844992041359,2.04007041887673));
#776=CARTESIAN_POINT('',(14.9983846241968,-0.253498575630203,2.00804626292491));
#777=CARTESIAN_POINT('',(15.0000023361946,-0.126771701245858,1.9999953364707));
#778=CARTESIAN_POINT('',(15.,0.,2.));
#779=B_SPLINE_CURVE_WITH_KNOTS('',3,(#701,#702,#703,#704,#705,#706,#707,#708,#709,#710,#711,
#712,#713,#714,#715,#716,#717,#718,#719,#720,#721,#722,#723,#724,#725,#726,#727,#728,#729,#730,
#731,#732,#733,#734,#735,#736,#737,#738,#739,#740,#741,#742,#743,#744,#745,#746,#747,#748,#749,
#750,#751,#752,#753,#754,#755,#756,#757,#758,#759,#760,#761,#762,#763,#764,#765,#766,#767,#768,
#769,#770,#771,#772,#773,#774,#775,#776,#777,#778),.UNSPECIFIED.,.T.,.F.,(4,2,2,2,2,2,2,2,2,2,2,
2,2,2,2,2,2,2,2,2,2,2,2,2,2,2,2,2,2,2,2,2,2,2,2,2,2,2,4),(0.,0.499728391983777,
0.999853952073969,1.49950120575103,1.99911870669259,2.50479801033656,3.0105167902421,
3.52083585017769,4.03110448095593,4.53468555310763,5.03821512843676,5.53415181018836,
6.0301121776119,6.52942470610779,7.02879464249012,7.53714757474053,8.04550702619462,
8.55465824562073,9.0637477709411,9.56432207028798,10.064868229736,10.5609136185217,
11.0569961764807,11.5591519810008,12.0613616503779,12.5712188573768,13.081055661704,
13.5882114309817,14.0953010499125,14.5931916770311,15.0910783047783,15.5877588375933,
16.084481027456,16.5896422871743,17.0949196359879,17.6054849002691,18.1155886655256,
18.4955632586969,18.8755257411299),.UNSPECIFIED.);
#780=CARTESIAN_POINT('',(15.,0.,2.));
#781=VERTEX_POINT('',#780);
#782=EDGE_CURVE('E9',#781,#781,#779,.T.);
#783=ORIENTED_EDGE('',*,*,#782,.F.);
#784=EDGE_LOOP('',(#783));
#785=FACE_BOUND('',#784,.T.);
#786=ORIENTED_EDGE('',*,*,#691,.T.);
#787=EDGE_LOOP('',(#786));
#788=FACE_BOUND('',#787,.T.);
#789=CARTESIAN_POINT('',(0.,0.,0.200000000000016));
#790=DIRECTION('',(0.,0.,-1.));
#791=DIRECTION('',(-1.,0.,0.));
#792=AXIS2_PLACEMENT_3D('',#789,#790,#791);
#793=CIRCLE('',#792,15.);
#794=CARTESIAN_POINT('',(-15.,0.,0.200000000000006));
#795=VERTEX_POINT('',#794);
#796=EDGE_CURVE('E381',#795,#795,#793,.F.);
#797=ORIENTED_EDGE('',*,*,#796,.T.);
#798=EDGE_LOOP('',(#797));
#799=FACE_BOUND('',#798,.T.);
#800=ADVANCED_FACE('F369',(#785,#788,#799),#700,.T.);
#801=CARTESIAN_POINT('',(-13.,0.,0.2));
#802=DIRECTION('',(0.,0.,-1.));
#803=DIRECTION('',(-1.,0.,0.));
#804=AXIS2_PLACEMENT_3D('',#801,#802,#803);
#805=PLANE('',#804);
#806=CARTESIAN_POINT('',(0.,0.,0.200000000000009));
#807=DIRECTION('',(0.,0.,-1.));
#808=DIRECTION('',(-1.,0.,0.));
#809=AXIS2_PLACEMENT_3D('',#806,#807,#808);
#810=CIRCLE('',#809,11.);
#811=CARTESIAN_POINT('',(-11.,0.,0.200000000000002));
#812=VERTEX_POINT('',#811);
#813=EDGE_CURVE('E940',#812,#812,#810,.F.);
#814=ORIENTED_EDGE('',*,*,#813,.T.);
#815=EDGE_LOOP('',(#814));
#816=FACE_BOUND('',#815,.T.);
#817=ORIENTED_EDGE('',*,*,#796,.F.);
#818=EDGE_LOOP('',(#817));
#819=FACE_BOUND('',#818,.T.);
#820=ADVANCED_FACE('F827',(#816,#819),#805,.T.);
#821=CARTESIAN_POINT('',(0.,0.,0.100000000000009));
#822=DIRECTION('',(0.,0.,-1.));
#823=DIRECTION('',(-1.,0.,0.));
#824=AXIS2_PLACEMENT_3D('',#821,#822,#823);
#825=CYLINDRICAL_SURFACE('',#824,11.);
#826=ORIENTED_EDGE('',*,*,#813,.F.);
#827=EDGE_LOOP('',(#826));
#828=FACE_BOUND('',#827,.T.);
#829=CARTESIAN_POINT('',(0.,0.,0.));
#830=DIRECTION('',(0.,0.,-1.));
#831=DIRECTION('',(-1.,0.,0.));
#832=AXIS2_PLACEMENT_3D('',#829,#830,#831);
#833=CIRCLE('',#832,11.);
#834=CARTESIAN_POINT('',(-11.,0.,0.));
#835=VERTEX_POINT('',#834);
#836=EDGE_CURVE('E938',#835,#835,#833,.F.);
#837=ORIENTED_EDGE('',*,*,#836,.T.);
#838=EDGE_LOOP('',(#837));
#839=FACE_BOUND('',#838,.T.);
#840=ADVANCED_FACE('F819',(#828,#839),#825,.T.);
#841=CARTESIAN_POINT('',(-8.16666666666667,0.,0.));
#842=DIRECTION('',(0.,0.,-1.));
#843=DIRECTION('',(0.,-1.,0.));
#844=AXIS2_PLACEMENT_3D('',#841,#842,#843);
#845=PLANE('',#844);
#846=CARTESIAN_POINT('',(0.,0.,-5.68200305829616E-11));
#847=DIRECTION('',(0.,0.,-1.));
#848=DIRECTION('',(-1.,0.,0.));
#849=AXIS2_PLACEMENT_3D('',#846,#847,#848);
#850=CIRCLE('',#849,5.33333333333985);
#851=CARTESIAN_POINT('',(-5.33333333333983,0.,-5.68235091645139E-11));
#852=VERTEX_POINT('',#851);
#853=EDGE_CURVE('E385',#852,#852,#850,.F.);
#854=ORIENTED_EDGE('',*,*,#853,.T.);
#855=EDGE_LOOP('',(#854));
#856=FACE_BOUND('',#855,.T.);
#857=ORIENTED_EDGE('',*,*,#836,.F.);
#858=EDGE_LOOP('',(#857));
#859=FACE_BOUND('',#858,.T.);
#860=ADVANCED_FACE('F811',(#856,#859),#845,.T.);
#861=CARTESIAN_POINT('',(0.,0.,-5.68391125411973E-11));
#862=DIRECTION('',(0.,0.,-1.));
#863=DIRECTION('',(-1.,0.,0.));
#864=AXIS2_PLACEMENT_3D('',#861,#862,#863);
#865=CONICAL_SURFACE('',#864,5.33333333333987,0.785398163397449);
#866=ORIENTED_EDGE('',*,*,#853,.F.);
#867=EDGE_LOOP('',(#866));
#868=FACE_BOUND('',#867,.T.);
#869=CARTESIAN_POINT('',(0.,0.,0.33333333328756));
#870=DIRECTION('',(0.,0.,-1.));
#871=DIRECTION('',(-1.,0.,0.));
#872=AXIS2_PLACEMENT_3D('',#869,#870,#871);
#873=CIRCLE('',#872,4.99999999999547);
#874=CARTESIAN_POINT('',(-4.99999999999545,0.,0.333333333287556));
#875=VERTEX_POINT('',#874);
#876=EDGE_CURVE('E382',#875,#875,#873,.T.);
#877=ORIENTED_EDGE('',*,*,#876,.F.);
#878=EDGE_LOOP('',(#877));
#879=FACE_BOUND('',#878,.T.);
#880=ADVANCED_FACE('F803',(#868,#879),#865,.F.);
#881=CARTESIAN_POINT('',(0.,0.,11.));
#882=DIRECTION('',(0.,0.,-1.));
#883=DIRECTION('',(-1.,0.,0.));
#884=AXIS2_PLACEMENT_3D('',#881,#882,#883);
#885=CYLINDRICAL_SURFACE('',#884,5.);
#886=CARTESIAN_POINT('',(5.,0.,2.5));
#887=CARTESIAN_POINT('',(4.99999177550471,0.131426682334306,2.50000966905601));
#888=CARTESIAN_POINT('',(4.99476199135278,0.263015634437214,2.51042556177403));
#889=CARTESIAN_POINT('',(4.97435418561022,0.522301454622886,2.55163182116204));
#890=CARTESIAN_POINT('',(4.95915727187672,0.64999044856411,2.582460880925));
#891=CARTESIAN_POINT('',(4.92040690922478,0.897333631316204,2.66298462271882));
#892=CARTESIAN_POINT('',(4.89688595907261,1.01701694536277,2.71260598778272));
#893=CARTESIAN_POINT('',(4.84364443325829,1.24618160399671,2.82892652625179));
#894=CARTESIAN_POINT('',(4.81392434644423,1.3556637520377,2.89562435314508));
#895=CARTESIAN_POINT('',(4.74890645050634,1.56876952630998,3.04879313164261));
#896=CARTESIAN_POINT('',(4.71337997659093,1.67163802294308,3.13621620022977));
#897=CARTESIAN_POINT('',(4.64149925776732,1.86194861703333,3.32630369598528));
#898=CARTESIAN_POINT('',(4.60514440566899,1.94937895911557,3.42897962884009));
#899=CARTESIAN_POINT('',(4.53247377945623,2.11312999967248,3.65620837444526));
#900=CARTESIAN_POINT('',(4.49637967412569,2.18806333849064,3.781840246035));
#901=CARTESIAN_POINT('',(4.43214946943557,2.31542056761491,4.04591833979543));
#902=CARTESIAN_POINT('',(4.40400769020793,2.36786053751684,4.18435532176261));
#903=CARTESIAN_POINT('',(4.36144667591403,2.44533110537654,4.4616627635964));
#904=CARTESIAN_POINT('',(4.34630678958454,2.47181464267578,4.60001113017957));
#905=CARTESIAN_POINT('',(4.32954724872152,2.50106748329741,4.8799470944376));
#906=CARTESIAN_POINT('',(4.32791423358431,2.50386022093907,5.02153135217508));
#907=CARTESIAN_POINT('',(4.33777325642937,2.48671821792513,5.28571506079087));
#908=CARTESIAN_POINT('',(4.34771909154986,2.46946139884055,5.40856007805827));
#909=CARTESIAN_POINT('',(4.37690571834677,2.41734962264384,5.64930477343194));
#910=CARTESIAN_POINT('',(4.39614947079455,2.38248905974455,5.76720286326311));
#911=CARTESIAN_POINT('',(4.4421869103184,2.29552445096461,5.99807283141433));
#912=CARTESIAN_POINT('',(4.46914601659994,2.24303766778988,6.11086599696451));
#913=CARTESIAN_POINT('',(4.52758510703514,2.12260421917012,6.32658573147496));
#914=CARTESIAN_POINT('',(4.55906711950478,2.05465060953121,6.42950783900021));
#915=CARTESIAN_POINT('',(4.62782894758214,1.89516513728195,6.63630313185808));
#916=CARTESIAN_POINT('',(4.66533775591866,1.8017361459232,6.73864218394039));
#917=CARTESIAN_POINT('',(4.7386905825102,1.59888894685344,6.92683854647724));
#918=CARTESIAN_POINT('',(4.77453379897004,1.48946314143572,7.01268798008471));
#919=CARTESIAN_POINT('',(4.8425496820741,1.25129126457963,7.16921415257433));
#920=CARTESIAN_POINT('',(4.87447460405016,1.12188397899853,7.23900118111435));
#921=CARTESIAN_POINT('',(4.9289470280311,0.851165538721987,7.35524257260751));
#922=CARTESIAN_POINT('',(4.95150197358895,0.709863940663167,7.4017154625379));
#923=CARTESIAN_POINT('',(4.98310834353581,0.431916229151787,7.46618850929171));
#924=CARTESIAN_POINT('',(4.99312345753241,0.29585382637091,7.48622808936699));
#925=CARTESIAN_POINT('',(5.00182533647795,0.0219489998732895,7.50366182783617));
#926=CARTESIAN_POINT('',(5.00051746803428,-0.115892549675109,7.5010667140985));
#927=CARTESIAN_POINT('',(4.9872798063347,-0.378082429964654,7.47448327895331));
#928=CARTESIAN_POINT('',(4.97618114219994,-0.502648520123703,7.45216866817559));
#929=CARTESIAN_POINT('',(4.94555428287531,-0.74601723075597,7.38940482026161));
#930=CARTESIAN_POINT('',(4.92602515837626,-0.864819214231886,7.34895358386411));
#931=CARTESIAN_POINT('',(4.87960628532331,-1.09722152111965,7.25000383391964));
#932=CARTESIAN_POINT('',(4.85252204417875,-1.2105759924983,7.19102237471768));
#933=CARTESIAN_POINT('',(4.79359935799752,-1.42615340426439,7.05723116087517));
#934=CARTESIAN_POINT('',(4.76175888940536,-1.52837157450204,6.98241466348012));
#935=CARTESIAN_POINT('',(4.69270553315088,-1.72941922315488,6.81059893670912));
#936=CARTESIAN_POINT('',(4.6552721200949,-1.82693019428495,6.7121428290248));
#937=CARTESIAN_POINT('',(4.58155978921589,-2.0046408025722,6.50018712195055));
#938=CARTESIAN_POINT('',(4.54528168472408,-2.08482846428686,6.38667720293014));
#939=CARTESIAN_POINT('',(4.47627980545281,-2.22926978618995,6.14089086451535));
#940=CARTESIAN_POINT('',(4.44381323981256,-2.29256373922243,6.00797183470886));
#941=CARTESIAN_POINT('',(4.38935180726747,-2.39520706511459,5.73122483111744));
#942=CARTESIAN_POINT('',(4.36734345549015,-2.43458729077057,5.58741118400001));
#943=CARTESIAN_POINT('',(4.33903752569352,-2.48465421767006,5.30772444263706));
#944=CARTESIAN_POINT('',(4.33143458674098,-2.4977324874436,5.17241436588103));
#945=CARTESIAN_POINT('',(4.32913386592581,-2.50172288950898,4.90138233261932));
#946=CARTESIAN_POINT('',(4.33443049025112,-2.49264462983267,4.76566058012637));
#947=CARTESIAN_POINT('',(4.35594655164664,-2.45481530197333,4.51129124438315));
#948=CARTESIAN_POINT('',(4.37107736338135,-2.42802074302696,4.39224881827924));
#949=CARTESIAN_POINT('',(4.40927540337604,-2.35793843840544,4.16047970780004));
#950=CARTESIAN_POINT('',(4.43234518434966,-2.31464538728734,4.04775506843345));
#951=CARTESIAN_POINT('',(4.48571326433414,-2.2095391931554,3.82343784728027));
#952=CARTESIAN_POINT('',(4.51639307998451,-2.14667719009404,3.71243014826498));
#953=CARTESIAN_POINT('',(4.58088327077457,-2.0053780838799,3.50181375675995));
#954=CARTESIAN_POINT('',(4.61469526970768,-1.92693287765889,3.40221103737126));
#955=CARTESIAN_POINT('',(4.68655816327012,-1.74550556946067,3.20464463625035));
#956=CARTESIAN_POINT('',(4.72462491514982,-1.6407002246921,3.10835063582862));
#957=CARTESIAN_POINT('',(4.79694347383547,-1.41539785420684,2.93434415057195));
#958=CARTESIAN_POINT('',(4.83119321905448,-1.29489242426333,2.8566416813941));
#959=CARTESIAN_POINT('',(4.89245149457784,-1.03978808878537,2.72190302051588));
#960=CARTESIAN_POINT('',(4.9194071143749,-0.905095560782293,2.66501683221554));
#961=CARTESIAN_POINT('',(4.95177960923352,-0.696328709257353,2.5978161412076));
#962=CARTESIAN_POINT('',(4.96122314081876,-0.62567041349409,2.57844460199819));
#963=CARTESIAN_POINT('',(4.97717127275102,-0.482623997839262,2.54593405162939));
#964=CARTESIAN_POINT('',(4.98367766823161,-0.410236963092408,2.53279123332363));
#965=CARTESIAN_POINT('',(4.99238200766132,-0.281518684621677,2.51526252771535));
#966=CARTESIAN_POINT('',(4.99523288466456,-0.225408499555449,2.50954506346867));
#967=CARTESIAN_POINT('',(4.9990436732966,-0.112875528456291,2.50191167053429));
#968=CARTESIAN_POINT('',(5.00000353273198,-0.056452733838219,2.49999584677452));
#969=CARTESIAN_POINT('',(5.,0.,2.5));
#970=B_SPLINE_CURVE_WITH_KNOTS('',3,(#886,#887,#888,#889,#890,#891,#892,#893,#894,#895,#896,
#897,#898,#899,#900,#901,#902,#903,#904,#905,#906,#907,#908,#909,#910,#911,#912,#913,#914,#915,
#916,#917,#918,#919,#920,#921,#922,#923,#924,#925,#926,#927,#928,#929,#930,#931,#932,#933,#934,
#935,#936,#937,#938,#939,#940,#941,#942,#943,#944,#945,#946,#947,#948,#949,#950,#951,#952,#953,
#954,#955,#956,#957,#958,#959,#960,#961,#962,#963,#964,#965,#966,#967,#968,#969),.UNSPECIFIED.,
.T.,.F.,(4,2,2,2,2,2,2,2,2,2,2,2,2,2,2,2,2,2,2,2,2,2,2,2,2,2,2,2,2,2,2,2,2,2,2,2,2,2,2,2,2,4),
(0.,0.394060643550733,0.788870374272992,1.18215538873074,1.57540940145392,1.99245439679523,
2.40981559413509,2.85954316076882,3.30894869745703,3.73145030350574,4.15353393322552,
4.52514281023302,4.89687009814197,5.27725600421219,5.65781303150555,6.08662353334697,
6.51563836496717,6.96457555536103,7.41315542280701,7.82458226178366,8.23581411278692,
8.61517266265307,8.99457304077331,9.38482140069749,9.7752362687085,10.2039902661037,
10.6330397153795,11.0828670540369,11.53211279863,11.9382326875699,12.3441764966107,
12.7114482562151,13.0788382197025,13.4709114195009,13.8631890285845,14.303131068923,
14.7433095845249,15.1866003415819,15.407934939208,15.6291340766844,15.7983933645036,
15.9676573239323),.UNSPECIFIED.);
#971=CARTESIAN_POINT('',(5.,0.,2.5));
#972=VERTEX_POINT('',#971);
#973=EDGE_CURVE('E100',#972,#972,#970,.T.);
#974=ORIENTED_EDGE('',*,*,#973,.T.);
#975=EDGE_LOOP('',(#974));
#976=FACE_BOUND('',#975,.T.);
#977=ORIENTED_EDGE('',*,*,#876,.T.);
#978=EDGE_LOOP('',(#977));
#979=FACE_BOUND('',#978,.T.);
#980=CARTESIAN_POINT('',(0.,0.,21.6666666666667));
#981=DIRECTION('',(0.,0.,-1.));
#982=DIRECTION('',(-1.,0.,0.));
#983=AXIS2_PLACEMENT_3D('',#980,#981,#982);
#984=CIRCLE('',#983,5.);
#985=CARTESIAN_POINT('',(-4.99999999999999,0.,21.6666666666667));
#986=VERTEX_POINT('',#985);
#987=EDGE_CURVE('E386',#986,#986,#984,.T.);
#988=ORIENTED_EDGE('',*,*,#987,.F.);
#989=EDGE_LOOP('',(#988));
#990=FACE_BOUND('',#989,.T.);
#991=ADVANCED_FACE('F795',(#976,#979,#990),#885,.F.);
#992=CARTESIAN_POINT('',(0.,0.,21.9999999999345));
#993=DIRECTION('',(0.,0.,1.));
#994=DIRECTION('',(1.,0.,0.));
#995=AXIS2_PLACEMENT_3D('',#992,#993,#994);
#996=CONICAL_SURFACE('',#995,5.33333333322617,0.785398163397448);
#997=ORIENTED_EDGE('',*,*,#987,.T.);
#998=EDGE_LOOP('',(#997));
#999=FACE_BOUND('',#998,.T.);
#1000=CARTESIAN_POINT('',(0.,0.,21.9999999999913));
#1001=DIRECTION('',(0.,0.,1.));
#1002=DIRECTION('',(1.,0.,0.));
#1003=AXIS2_PLACEMENT_3D('',#1000,#1001,#1002);
#1004=CIRCLE('',#1003,5.33333333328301);
#1005=CARTESIAN_POINT('',(5.33333333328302,0.,21.9999999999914));
#1006=VERTEX_POINT('',#1005);
#1007=EDGE_CURVE('E240',#1006,#1006,#1004,.F.);
#1008=ORIENTED_EDGE('',*,*,#1007,.F.);
#1009=EDGE_LOOP('',(#1008));
#1010=FACE_BOUND('',#1009,.T.);
#1011=ADVANCED_FACE('F787',(#999,#1010),#996,.F.);
#1012=CARTESIAN_POINT('',(-7.66666666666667,0.,22.));
#1013=DIRECTION('',(0.,0.,1.));
#1014=DIRECTION('',(0.,1.,0.));
#1015=AXIS2_PLACEMENT_3D('',#1012,#1013,#1014);
#1016=PLANE('',#1015);
#1017=CARTESIAN_POINT('',(0.,0.,22.));
#1018=DIRECTION('',(0.,0.,-1.));
#1019=DIRECTION('',(-1.,0.,0.));
#1020=AXIS2_PLACEMENT_3D('',#1017,#1018,#1019);
#1021=CIRCLE('',#1020,10.);
#1022=CARTESIAN_POINT('',(-9.99999999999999,0.,22.));
#1023=VERTEX_POINT('',#1022);
#1024=EDGE_CURVE('E235',#1023,#1023,#1021,.F.);
#1025=ORIENTED_EDGE('',*,*,#1024,.T.);
#1026=EDGE_LOOP('',(#1025));
#1027=FACE_BOUND('',#1026,.T.);
#1028=ORIENTED_EDGE('',*,*,#1007,.T.);
#1029=EDGE_LOOP('',(#1028));
#1030=FACE_BOUND('',#1029,.T.);
#1031=ADVANCED_FACE('F780',(#1027,#1030),#1016,.T.);
#1032=CARTESIAN_POINT('',(0.,0.,23.1));
#1033=DIRECTION('',(0.,0.,-1.));
#1034=DIRECTION('',(-1.,0.,0.));
#1035=AXIS2_PLACEMENT_3D('',#1032,#1033,#1034);
#1036=CYLINDRICAL_SURFACE('',#1035,10.);
#1037=ORIENTED_EDGE('',*,*,#1024,.F.);
#1038=EDGE_LOOP('',(#1037));
#1039=FACE_BOUND('',#1038,.T.);
#1040=CARTESIAN_POINT('',(0.,0.,24.2));
#1041=DIRECTION('',(0.,0.,-1.));
#1042=DIRECTION('',(-1.,0.,0.));
#1043=AXIS2_PLACEMENT_3D('',#1040,#1041,#1042);
#1044=CIRCLE('',#1043,10.);
#1045=CARTESIAN_POINT('',(-10.,0.,24.2));
#1046=VERTEX_POINT('',#1045);
#1047=EDGE_CURVE('E232',#1046,#1046,#1044,.T.);
#1048=ORIENTED_EDGE('',*,*,#1047,.F.);
#1049=EDGE_LOOP('',(#1048));
#1050=FACE_BOUND('',#1049,.T.);
#1051=ADVANCED_FACE('F774',(#1039,#1050),#1036,.F.);
#1052=CARTESIAN_POINT('',(-5.,0.,24.2));
#1053=DIRECTION('',(0.,0.,-1.));
#1054=DIRECTION('',(0.,-1.,0.));
#1055=AXIS2_PLACEMENT_3D('',#1052,#1053,#1054);
#1056=PLANE('',#1055);
#1057=ORIENTED_EDGE('',*,*,#1047,.T.);
#1058=EDGE_LOOP('',(#1057));
#1059=FACE_BOUND('',#1058,.T.);
#1060=ADVANCED_FACE('F215',(#1059),#1056,.T.);
#1061=CARTESIAN_POINT('',(39.,0.,21.6135000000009));
#1062=DIRECTION('',(0.,0.,1.));
#1063=DIRECTION('',(0.,1.,0.));
#1064=AXIS2_PLACEMENT_3D('',#1061,#1062,#1063);
#1065=CONICAL_SURFACE('',#1064,2.99999999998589,0.785398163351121);
#1066=CARTESIAN_POINT('',(39.,0.,21.000000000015));
#1067=DIRECTION('',(0.,0.,1.));
#1068=DIRECTION('',(0.,1.,0.));
#1069=AXIS2_PLACEMENT_3D('',#1066,#1067,#1068);
#1070=CIRCLE('',#1069,2.3865000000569);
#1071=CARTESIAN_POINT('',(39.,2.3865000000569,21.000000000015));
#1072=VERTEX_POINT('',#1071);
#1073=EDGE_CURVE('E127',#1072,#1072,#1070,.T.);
#1074=ORIENTED_EDGE('',*,*,#1073,.T.);
#1075=EDGE_LOOP('',(#1074));
#1076=FACE_BOUND('',#1075,.T.);
#1077=ORIENTED_EDGE('',*,*,#409,.F.);
#1078=EDGE_LOOP('',(#1077));
#1079=FACE_BOUND('',#1078,.T.);
#1080=ADVANCED_FACE('F565',(#1076,#1079),#1065,.T.);
#1081=CARTESIAN_POINT('',(39.,-1.19325,21.));
#1082=DIRECTION('',(0.,0.,-1.));
#1083=DIRECTION('',(0.,-1.,0.));
#1084=AXIS2_PLACEMENT_3D('',#1081,#1082,#1083);
#1085=PLANE('',#1084);
#1086=ORIENTED_EDGE('',*,*,#1073,.F.);
#1087=EDGE_LOOP('',(#1086));
#1088=FACE_BOUND('',#1087,.T.);
#1089=DIRECTION('',(0.,-1.,0.));
#1090=VECTOR('',#1089,1.);
#1091=CARTESIAN_POINT('',(37.5,-0.866025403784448,21.));
#1092=LINE('',#1091,#1090);
#1093=CARTESIAN_POINT('',(37.5,0.86602540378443,21.));
#1094=VERTEX_POINT('',#1093);
#1095=CARTESIAN_POINT('',(37.5,-0.866025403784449,21.));
#1096=VERTEX_POINT('',#1095);
#1097=EDGE_CURVE('E157',#1094,#1096,#1092,.T.);
#1098=ORIENTED_EDGE('',*,*,#1097,.T.);
#1099=DIRECTION('',(0.866025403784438,-0.5,0.));
#1100=VECTOR('',#1099,1.);
#1101=CARTESIAN_POINT('',(37.5,-0.866025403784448,21.));
#1102=LINE('',#1101,#1100);
#1103=CARTESIAN_POINT('',(39.,-1.73205080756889,21.));
#1104=VERTEX_POINT('',#1103);
#1105=EDGE_CURVE('E129',#1096,#1104,#1102,.T.);
#1106=ORIENTED_EDGE('',*,*,#1105,.T.);
#1107=DIRECTION('',(0.866025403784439,0.5,0.));
#1108=VECTOR('',#1107,1.);
#1109=CARTESIAN_POINT('',(40.5,-0.866025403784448,21.));
#1110=LINE('',#1109,#1108);
#1111=CARTESIAN_POINT('',(40.5,-0.866025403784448,21.));
#1112=VERTEX_POINT('',#1111);
#1113=EDGE_CURVE('E155',#1104,#1112,#1110,.T.);
#1114=ORIENTED_EDGE('',*,*,#1113,.T.);
#1115=DIRECTION('',(0.,1.,0.));
#1116=VECTOR('',#1115,1.);
#1117=CARTESIAN_POINT('',(40.5,0.86602540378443,21.));
#1118=LINE('',#1117,#1116);
#1119=CARTESIAN_POINT('',(40.5,0.866025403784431,21.));
#1120=VERTEX_POINT('',#1119);
#1121=EDGE_CURVE('E95',#1112,#1120,#1118,.T.);
#1122=ORIENTED_EDGE('',*,*,#1121,.T.);
#1123=DIRECTION('',(-0.866025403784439,0.5,0.));
#1124=VECTOR('',#1123,1.);
#1125=CARTESIAN_POINT('',(39.,1.73205080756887,21.));
#1126=LINE('',#1125,#1124);
#1127=CARTESIAN_POINT('',(39.,1.73205080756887,21.));
#1128=VERTEX_POINT('',#1127);
#1129=EDGE_CURVE('E88',#1120,#1128,#1126,.T.);
#1130=ORIENTED_EDGE('',*,*,#1129,.T.);
#1131=DIRECTION('',(-0.866025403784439,-0.5,0.));
#1132=VECTOR('',#1131,1.);
#1133=CARTESIAN_POINT('',(37.5,0.86602540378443,21.));
#1134=LINE('',#1133,#1132);
#1135=EDGE_CURVE('E92',#1128,#1094,#1134,.T.);
#1136=ORIENTED_EDGE('',*,*,#1135,.T.);
#1137=EDGE_LOOP('',(#1098,#1106,#1114,#1122,#1130,#1136));
#1138=FACE_BOUND('',#1137,.T.);
#1139=ADVANCED_FACE('F90',(#1088,#1138),#1085,.T.);
#1140=CARTESIAN_POINT('',(37.5,-0.866025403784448,21.));
#1141=DIRECTION('',(-1.,0.,0.));
#1142=DIRECTION('',(0.,-1.,0.));
#1143=AXIS2_PLACEMENT_3D('',#1140,#1141,#1142);
#1144=PLANE('',#1143);
#1145=DIRECTION('',(0.,0.,1.));
#1146=VECTOR('',#1145,1.);
#1147=CARTESIAN_POINT('',(37.5,-0.866025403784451,21.));
#1148=LINE('',#1147,#1146);
#1149=CARTESIAN_POINT('',(37.5,-0.866025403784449,24.));
#1150=VERTEX_POINT('',#1149);
#1151=EDGE_CURVE('E144',#1150,#1096,#1148,.F.);
#1152=ORIENTED_EDGE('',*,*,#1151,.T.);
#1153=ORIENTED_EDGE('',*,*,#1097,.F.);
#1154=DIRECTION('',(0.,0.,1.));
#1155=VECTOR('',#1154,1.);
#1156=CARTESIAN_POINT('',(37.5,0.86602540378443,21.));
#1157=LINE('',#1156,#1155);
#1158=CARTESIAN_POINT('',(37.5,0.86602540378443,24.));
#1159=VERTEX_POINT('',#1158);
#1160=EDGE_CURVE('E109',#1159,#1094,#1157,.F.);
#1161=ORIENTED_EDGE('',*,*,#1160,.F.);
#1162=DIRECTION('',(0.,1.,0.));
#1163=VECTOR('',#1162,1.);
#1164=CARTESIAN_POINT('',(37.5,0.,24.));
#1165=LINE('',#1164,#1163);
#1166=EDGE_CURVE('E150',#1159,#1150,#1165,.F.);
#1167=ORIENTED_EDGE('',*,*,#1166,.T.);
#1168=EDGE_LOOP('',(#1152,#1153,#1161,#1167));
#1169=FACE_BOUND('',#1168,.T.);
#1170=ADVANCED_FACE('F173',(#1169),#1144,.F.);
#1171=CARTESIAN_POINT('',(39.,-1.73205080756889,21.));
#1172=DIRECTION('',(-0.5,-0.866025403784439,0.));
#1173=DIRECTION('',(0.866025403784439,-0.5,0.));
#1174=AXIS2_PLACEMENT_3D('',#1171,#1172,#1173);
#1175=PLANE('',#1174);
#1176=DIRECTION('',(0.,0.,1.));
#1177=VECTOR('',#1176,1.);
#1178=CARTESIAN_POINT('',(39.,-1.73205080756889,21.));
#1179=LINE('',#1178,#1177);
#1180=CARTESIAN_POINT('',(39.,-1.73205080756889,24.));
#1181=VERTEX_POINT('',#1180);
#1182=EDGE_CURVE('E139',#1104,#1181,#1179,.T.);
#1183=ORIENTED_EDGE('',*,*,#1182,.F.);
#1184=ORIENTED_EDGE('',*,*,#1105,.F.);
#1185=ORIENTED_EDGE('',*,*,#1151,.F.);
#1186=DIRECTION('',(0.866025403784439,-0.5,0.));
#1187=VECTOR('',#1186,1.);
#1188=CARTESIAN_POINT('',(39.,-1.73205080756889,24.));
#1189=LINE('',#1188,#1187);
#1190=EDGE_CURVE('E135',#1181,#1150,#1189,.F.);
#1191=ORIENTED_EDGE('',*,*,#1190,.F.);
#1192=EDGE_LOOP('',(#1183,#1184,#1185,#1191));
#1193=FACE_BOUND('',#1192,.T.);
#1194=ADVANCED_FACE('F177',(#1193),#1175,.F.);
#1195=CARTESIAN_POINT('',(40.5,-0.866025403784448,21.));
#1196=DIRECTION('',(0.5,-0.866025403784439,0.));
#1197=DIRECTION('',(0.866025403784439,0.5,0.));
#1198=AXIS2_PLACEMENT_3D('',#1195,#1196,#1197);
#1199=PLANE('',#1198);
#1200=DIRECTION('',(0.,0.,1.));
#1201=VECTOR('',#1200,1.);
#1202=CARTESIAN_POINT('',(40.5,-0.866025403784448,21.));
#1203=LINE('',#1202,#1201);
#1204=CARTESIAN_POINT('',(40.5,-0.866025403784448,24.));
#1205=VERTEX_POINT('',#1204);
#1206=EDGE_CURVE('E152',#1112,#1205,#1203,.T.);
#1207=ORIENTED_EDGE('',*,*,#1206,.F.);
#1208=ORIENTED_EDGE('',*,*,#1113,.F.);
#1209=ORIENTED_EDGE('',*,*,#1182,.T.);
#1210=DIRECTION('',(0.866025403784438,0.5,0.));
#1211=VECTOR('',#1210,1.);
#1212=CARTESIAN_POINT('',(39.,-1.73205080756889,24.));
#1213=LINE('',#1212,#1211);
#1214=EDGE_CURVE('E147',#1181,#1205,#1213,.T.);
#1215=ORIENTED_EDGE('',*,*,#1214,.T.);
#1216=EDGE_LOOP('',(#1207,#1208,#1209,#1215));
#1217=FACE_BOUND('',#1216,.T.);
#1218=ADVANCED_FACE('F179',(#1217),#1199,.F.);
#1219=CARTESIAN_POINT('',(40.5,0.86602540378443,21.));
#1220=DIRECTION('',(1.,0.,0.));
#1221=DIRECTION('',(0.,1.,0.));
#1222=AXIS2_PLACEMENT_3D('',#1219,#1220,#1221);
#1223=PLANE('',#1222);
#1224=DIRECTION('',(0.,0.,1.));
#1225=VECTOR('',#1224,1.);
#1226=CARTESIAN_POINT('',(40.5,0.86602540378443,21.));
#1227=LINE('',#1226,#1225);
#1228=CARTESIAN_POINT('',(40.5,0.866025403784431,24.));
#1229=VERTEX_POINT('',#1228);
#1230=EDGE_CURVE('E162',#1120,#1229,#1227,.T.);
#1231=ORIENTED_EDGE('',*,*,#1230,.F.);
#1232=ORIENTED_EDGE('',*,*,#1121,.F.);
#1233=ORIENTED_EDGE('',*,*,#1206,.T.);
#1234=DIRECTION('',(0.,1.,0.));
#1235=VECTOR('',#1234,1.);
#1236=CARTESIAN_POINT('',(40.5,0.86602540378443,24.));
#1237=LINE('',#1236,#1235);
#1238=EDGE_CURVE('E160',#1229,#1205,#1237,.F.);
#1239=ORIENTED_EDGE('',*,*,#1238,.F.);
#1240=EDGE_LOOP('',(#1231,#1232,#1233,#1239));
#1241=FACE_BOUND('',#1240,.T.);
#1242=ADVANCED_FACE('F165',(#1241),#1223,.F.);
#1243=CARTESIAN_POINT('',(39.,1.73205080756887,21.));
#1244=DIRECTION('',(0.5,0.866025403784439,0.));
#1245=DIRECTION('',(-0.866025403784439,0.5,0.));
#1246=AXIS2_PLACEMENT_3D('',#1243,#1244,#1245);
#1247=PLANE('',#1246);
#1248=DIRECTION('',(0.,0.,1.));
#1249=VECTOR('',#1248,1.);
#1250=CARTESIAN_POINT('',(39.,1.73205080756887,21.));
#1251=LINE('',#1250,#1249);
#1252=CARTESIAN_POINT('',(39.,1.73205080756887,24.));
#1253=VERTEX_POINT('',#1252);
#1254=EDGE_CURVE('E103',#1253,#1128,#1251,.F.);
#1255=ORIENTED_EDGE('',*,*,#1254,.T.);
#1256=ORIENTED_EDGE('',*,*,#1129,.F.);
#1257=ORIENTED_EDGE('',*,*,#1230,.T.);
#1258=DIRECTION('',(-0.866025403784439,0.5,0.));
#1259=VECTOR('',#1258,1.);
#1260=CARTESIAN_POINT('',(39.,1.73205080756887,24.));
#1261=LINE('',#1260,#1259);
#1262=EDGE_CURVE('E99',#1253,#1229,#1261,.F.);
#1263=ORIENTED_EDGE('',*,*,#1262,.F.);
#1264=EDGE_LOOP('',(#1255,#1256,#1257,#1263));
#1265=FACE_BOUND('',#1264,.T.);
#1266=ADVANCED_FACE('F17',(#1265),#1247,.F.);
#1267=CARTESIAN_POINT('',(37.5,0.86602540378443,21.));
#1268=DIRECTION('',(-0.5,0.866025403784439,0.));
#1269=DIRECTION('',(-0.866025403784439,-0.5,0.));
#1270=AXIS2_PLACEMENT_3D('',#1267,#1268,#1269);
#1271=PLANE('',#1270);
#1272=ORIENTED_EDGE('',*,*,#1160,.T.);
#1273=ORIENTED_EDGE('',*,*,#1135,.F.);
#1274=ORIENTED_EDGE('',*,*,#1254,.F.);
#1275=DIRECTION('',(-0.866025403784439,-0.5,0.));
#1276=VECTOR('',#1275,1.);
#1277=CARTESIAN_POINT('',(37.5,0.86602540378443,24.));
#1278=LINE('',#1277,#1276);
#1279=EDGE_CURVE('E111',#1159,#1253,#1278,.F.);
#1280=ORIENTED_EDGE('',*,*,#1279,.F.);
#1281=EDGE_LOOP('',(#1272,#1273,#1274,#1280));
#1282=FACE_BOUND('',#1281,.T.);
#1283=ADVANCED_FACE('F107',(#1282),#1271,.F.);
#1284=CARTESIAN_POINT('',(39.,0.,24.));
#1285=DIRECTION('',(0.,0.,1.));
#1286=DIRECTION('',(0.,1.,0.));
#1287=AXIS2_PLACEMENT_3D('',#1284,#1285,#1286);
#1288=PLANE('',#1287);
#1289=ORIENTED_EDGE('',*,*,#1190,.T.);
#1290=ORIENTED_EDGE('',*,*,#1166,.F.);
#1291=ORIENTED_EDGE('',*,*,#1279,.T.);
#1292=ORIENTED_EDGE('',*,*,#1262,.T.);
#1293=ORIENTED_EDGE('',*,*,#1238,.T.);
#1294=ORIENTED_EDGE('',*,*,#1214,.F.);
#1295=EDGE_LOOP('',(#1289,#1290,#1291,#1292,#1293,#1294));
#1296=FACE_BOUND('',#1295,.T.);
#1297=ADVANCED_FACE('F169',(#1296),#1288,.F.);
#1298=CARTESIAN_POINT('',(39.,0.,34.15));
#1299=DIRECTION('',(0.,0.,1.));
#1300=DIRECTION('',(0.,1.,0.));
#1301=AXIS2_PLACEMENT_3D('',#1298,#1299,#1300);
#1302=CYLINDRICAL_SURFACE('',#1301,5.4375);
#1303=ORIENTED_EDGE('',*,*,#31,.T.);
#1304=EDGE_LOOP('',(#1303));
#1305=FACE_BOUND('',#1304,.T.);
#1306=CARTESIAN_POINT('',(39.,0.,34.3));
#1307=DIRECTION('',(0.,0.,1.));
#1308=DIRECTION('',(0.,1.,0.));
#1309=AXIS2_PLACEMENT_3D('',#1306,#1307,#1308);
#1310=CIRCLE('',#1309,5.4375);
#1311=CARTESIAN_POINT('',(39.,5.43749999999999,34.3));
#1312=VERTEX_POINT('',#1311);
#1313=EDGE_CURVE('E121',#1312,#1312,#1310,.T.);
#1314=ORIENTED_EDGE('',*,*,#1313,.F.);
#1315=EDGE_LOOP('',(#1314));
#1316=FACE_BOUND('',#1315,.T.);
#1317=ADVANCED_FACE('F193',(#1305,#1316),#1302,.T.);
#1318=CARTESIAN_POINT('',(39.,-6.34375,34.3));
#1319=DIRECTION('',(0.,0.,-1.));
#1320=DIRECTION('',(0.,-1.,0.));
#1321=AXIS2_PLACEMENT_3D('',#1318,#1319,#1320);
#1322=PLANE('',#1321);
#1323=CARTESIAN_POINT('',(39.,0.,34.3));
#1324=DIRECTION('',(0.,0.,1.));
#1325=DIRECTION('',(0.,1.,0.));
#1326=AXIS2_PLACEMENT_3D('',#1323,#1324,#1325);
#1327=CIRCLE('',#1326,7.25);
#1328=CARTESIAN_POINT('',(39.,7.24999999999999,34.3));
#1329=VERTEX_POINT('',#1328);
#1330=EDGE_CURVE('E117',#1329,#1329,#1327,.T.);
#1331=ORIENTED_EDGE('',*,*,#1330,.F.);
#1332=EDGE_LOOP('',(#1331));
#1333=FACE_BOUND('',#1332,.T.);
#1334=ORIENTED_EDGE('',*,*,#1313,.T.);
#1335=EDGE_LOOP('',(#1334));
#1336=FACE_BOUND('',#1335,.T.);
#1337=ADVANCED_FACE('F619',(#1333,#1336),#1322,.T.);
#1338=CARTESIAN_POINT('',(39.,0.,43.65));
#1339=DIRECTION('',(0.,0.,1.));
#1340=DIRECTION('',(0.,1.,0.));
#1341=AXIS2_PLACEMENT_3D('',#1338,#1339,#1340);
#1342=CYLINDRICAL_SURFACE('',#1341,7.25);
#1343=ORIENTED_EDGE('',*,*,#1330,.T.);
#1344=EDGE_LOOP('',(#1343));
#1345=FACE_BOUND('',#1344,.T.);
#1346=CARTESIAN_POINT('',(39.,0.,53.));
#1347=DIRECTION('',(0.,0.,-1.));
#1348=DIRECTION('',(1.,0.,0.));
#1349=AXIS2_PLACEMENT_3D('',#1346,#1347,#1348);
#1350=CIRCLE('',#1349,7.25);
#1351=CARTESIAN_POINT('',(46.25,0.,53.));
#1352=VERTEX_POINT('',#1351);
#1353=EDGE_CURVE('E120',#1352,#1352,#1350,.F.);
#1354=ORIENTED_EDGE('',*,*,#1353,.F.);
#1355=EDGE_LOOP('',(#1354));
#1356=FACE_BOUND('',#1355,.T.);
#1357=ADVANCED_FACE('F209',(#1345,#1356),#1342,.T.);
#1358=CARTESIAN_POINT('',(39.,0.,54.75));
#1359=DIRECTION('',(0.,0.,-1.));
#1360=DIRECTION('',(1.,0.,0.));
#1361=AXIS2_PLACEMENT_3D('',#1358,#1359,#1360);
#1362=TOROIDAL_SURFACE('',#1361,7.25,1.75);
#1363=CARTESIAN_POINT('',(39.,0.,54.75));
#1364=DIRECTION('',(0.,0.,1.));
#1365=DIRECTION('',(0.,1.,0.));
#1366=AXIS2_PLACEMENT_3D('',#1363,#1364,#1365);
#1367=CIRCLE('',#1366,9.);
#1368=CARTESIAN_POINT('',(39.,8.99999999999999,54.75));
#1369=VERTEX_POINT('',#1368);
#1370=EDGE_CURVE('E227',#1369,#1369,#1367,.T.);
#1371=ORIENTED_EDGE('',*,*,#1370,.F.);
#1372=EDGE_LOOP('',(#1371));
#1373=FACE_BOUND('',#1372,.T.);
#1374=ORIENTED_EDGE('',*,*,#1353,.T.);
#1375=EDGE_LOOP('',(#1374));
#1376=FACE_BOUND('',#1375,.T.);
#1377=ADVANCED_FACE('F198',(#1373,#1376),#1362,.T.);
#1378=CARTESIAN_POINT('',(39.,0.,69.875));
#1379=DIRECTION('',(0.,0.,1.));
#1380=DIRECTION('',(0.,1.,0.));
#1381=AXIS2_PLACEMENT_3D('',#1378,#1379,#1380);
#1382=CYLINDRICAL_SURFACE('',#1381,9.);
#1383=CARTESIAN_POINT('',(39.,0.,85.));
#1384=DIRECTION('',(0.,0.,1.));
#1385=DIRECTION('',(0.,1.,0.));
#1386=AXIS2_PLACEMENT_3D('',#1383,#1384,#1385);
#1387=CIRCLE('',#1386,9.);
#1388=CARTESIAN_POINT('',(39.,8.99999999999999,85.));
#1389=VERTEX_POINT('',#1388);
#1390=EDGE_CURVE('E225',#1389,#1389,#1387,.F.);
#1391=ORIENTED_EDGE('',*,*,#1390,.T.);
#1392=EDGE_LOOP('',(#1391));
#1393=FACE_BOUND('',#1392,.T.);
#1394=ORIENTED_EDGE('',*,*,#1370,.T.);
#1395=EDGE_LOOP('',(#1394));
#1396=FACE_BOUND('',#1395,.T.);
#1397=ADVANCED_FACE('F195',(#1393,#1396),#1382,.T.);
#1398=CARTESIAN_POINT('',(39.,0.,85.));
#1399=DIRECTION('',(0.,0.,1.));
#1400=DIRECTION('',(0.,-1.,0.));
#1401=AXIS2_PLACEMENT_3D('',#1398,#1399,#1400);
#1402=SPHERICAL_SURFACE('',#1401,9.);
#1403=CARTESIAN_POINT('',(39.,0.,94.));
#1404=VERTEX_POINT('',#1403);
#1405=VERTEX_LOOP('',#1404);
#1406=FACE_BOUND('',#1405,.T.);
#1407=ORIENTED_EDGE('',*,*,#1390,.F.);
#1408=EDGE_LOOP('',(#1407));
#1409=FACE_BOUND('',#1408,.T.);
#1410=ADVANCED_FACE('F197',(#1406,#1409),#1402,.T.);
#1411=CARTESIAN_POINT('',(15.,0.,5.));
#1412=DIRECTION('',(1.,0.,0.));
#1413=DIRECTION('',(0.,0.,-1.));
#1414=AXIS2_PLACEMENT_3D('',#1411,#1412,#1413);
#1415=CYLINDRICAL_SURFACE('',#1414,2.5);
#1416=ORIENTED_EDGE('',*,*,#973,.F.);
#1417=EDGE_LOOP('',(#1416));
#1418=FACE_BOUND('',#1417,.T.);
#1419=CARTESIAN_POINT('',(11.,0.,5.));
#1420=DIRECTION('',(1.,0.,0.));
#1421=DIRECTION('',(0.,0.,-1.));
#1422=AXIS2_PLACEMENT_3D('',#1419,#1420,#1421);
#1423=CIRCLE('',#1422,2.5);
#1424=CARTESIAN_POINT('',(11.,0.,2.5));
#1425=VERTEX_POINT('',#1424);
#1426=EDGE_CURVE('E920',#1425,#1425,#1423,.T.);
#1427=ORIENTED_EDGE('',*,*,#1426,.T.);
#1428=EDGE_LOOP('',(#1427));
#1429=FACE_BOUND('',#1428,.T.);
#1430=ADVANCED_FACE('F206',(#1418,#1429),#1415,.F.);
#1431=CARTESIAN_POINT('',(11.,2.5,5.));
#1432=DIRECTION('',(-1.,0.,0.));
#1433=DIRECTION('',(0.,0.,1.));
#1434=AXIS2_PLACEMENT_3D('',#1431,#1432,#1433);
#1435=PLANE('',#1434);
#1436=ORIENTED_EDGE('',*,*,#1426,.F.);
#1437=EDGE_LOOP('',(#1436));
#1438=FACE_BOUND('',#1437,.T.);
#1439=CARTESIAN_POINT('',(11.,0.,5.));
#1440=DIRECTION('',(1.,0.,0.));
#1441=DIRECTION('',(0.,0.,-1.));
#1442=AXIS2_PLACEMENT_3D('',#1439,#1440,#1441);
#1443=CIRCLE('',#1442,3.);
#1444=CARTESIAN_POINT('',(11.,0.,2.));
#1445=VERTEX_POINT('',#1444);
#1446=EDGE_CURVE('E921',#1445,#1445,#1443,.T.);
#1447=ORIENTED_EDGE('',*,*,#1446,.T.);
#1448=EDGE_LOOP('',(#1447));
#1449=FACE_BOUND('',#1448,.T.);
#1450=ADVANCED_FACE('F888',(#1438,#1449),#1435,.F.);
#1451=CARTESIAN_POINT('',(15.,0.,5.));
#1452=DIRECTION('',(1.,0.,0.));
#1453=DIRECTION('',(0.,0.,-1.));
#1454=AXIS2_PLACEMENT_3D('',#1451,#1452,#1453);
#1455=CYLINDRICAL_SURFACE('',#1454,3.);
#1456=ORIENTED_EDGE('',*,*,#782,.T.);
#1457=EDGE_LOOP('',(#1456));
#1458=FACE_BOUND('',#1457,.T.);
#1459=ORIENTED_EDGE('',*,*,#1446,.F.);
#1460=EDGE_LOOP('',(#1459));
#1461=FACE_BOUND('',#1460,.T.);
#1462=ADVANCED_FACE('F885',(#1458,#1461),#1455,.F.);
#1463=CLOSED_SHELL('',(#46,#216,#247,#267,#287,#307,#316,#354,#376,#396,#424,#444,#464,#515,
#542,#563,#583,#603,#623,#643,#663,#675,#695,#800,#820,#840,#860,#880,#991,#1011,#1031,#1051,
#1060,#1080,#1139,#1170,#1194,#1218,#1242,#1266,#1283,#1297,#1317,#1337,#1357,#1377,#1397,#1410,
#1430,#1450,#1462));
#1464=CARTESIAN_POINT('',(39.,0.,33.35));
#1465=DIRECTION('',(0.,0.,1.));
#1466=DIRECTION('',(0.,1.,0.));
#1467=AXIS2_PLACEMENT_3D('',#1464,#1465,#1466);
#1468=CYLINDRICAL_SURFACE('',#1467,2.3865);
#1469=CARTESIAN_POINT('',(39.,0.,32.7));
#1470=DIRECTION('',(0.,0.,1.));
#1471=DIRECTION('',(0.,1.,0.));
#1472=AXIS2_PLACEMENT_3D('',#1469,#1470,#1471);
#1473=CIRCLE('',#1472,2.3865);
#1474=CARTESIAN_POINT('',(39.,2.38649999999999,32.7));
#1475=VERTEX_POINT('',#1474);
#1476=EDGE_CURVE('E126',#1475,#1475,#1473,.T.);
#1477=ORIENTED_EDGE('',*,*,#1476,.T.);
#1478=EDGE_LOOP('',(#1477));
#1479=FACE_BOUND('',#1478,.T.);
#1480=CARTESIAN_POINT('',(39.,0.,34.));
#1481=DIRECTION('',(0.,0.,1.));
#1482=DIRECTION('',(0.,1.,0.));
#1483=AXIS2_PLACEMENT_3D('',#1480,#1481,#1482);
#1484=CIRCLE('',#1483,2.3865);
#1485=CARTESIAN_POINT('',(39.,2.38649999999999,34.));
#1486=VERTEX_POINT('',#1485);
#1487=EDGE_CURVE('E124',#1486,#1486,#1484,.T.);
#1488=ORIENTED_EDGE('',*,*,#1487,.F.);
#1489=EDGE_LOOP('',(#1488));
#1490=FACE_BOUND('',#1489,.T.);
#1491=ADVANCED_FACE('F551',(#1479,#1490),#1468,.T.);
#1492=CARTESIAN_POINT('',(39.,-3.912,34.));
#1493=DIRECTION('',(0.,0.,-1.));
#1494=DIRECTION('',(0.,-1.,0.));
#1495=AXIS2_PLACEMENT_3D('',#1492,#1493,#1494);
#1496=PLANE('',#1495);
#1497=ORIENTED_EDGE('',*,*,#1487,.T.);
#1498=EDGE_LOOP('',(#1497));
#1499=FACE_BOUND('',#1498,.T.);
#1500=CARTESIAN_POINT('',(39.,0.,33.9999999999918));
#1501=DIRECTION('',(0.,0.,1.));
#1502=DIRECTION('',(0.,1.,0.));
#1503=AXIS2_PLACEMENT_3D('',#1500,#1501,#1502);
#1504=CIRCLE('',#1503,2.99999999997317);
#1505=CARTESIAN_POINT('',(39.,2.99999999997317,33.9999999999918));
#1506=VERTEX_POINT('',#1505);
#1507=EDGE_CURVE('E440',#1506,#1506,#1504,.F.);
#1508=ORIENTED_EDGE('',*,*,#1507,.T.);
#1509=EDGE_LOOP('',(#1508));
#1510=FACE_BOUND('',#1509,.T.);
#1511=ADVANCED_FACE('F546',(#1499,#1510),#1496,.T.);
#1512=CARTESIAN_POINT('',(39.,0.,32.0864999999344));
#1513=DIRECTION('',(0.,0.,-1.));
#1514=DIRECTION('',(0.,-1.,0.));
#1515=AXIS2_PLACEMENT_3D('',#1512,#1513,#1514);
#1516=CONICAL_SURFACE('',#1515,2.99999999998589,0.785398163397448);
#1517=ORIENTED_EDGE('',*,*,#1476,.F.);
#1518=EDGE_LOOP('',(#1517));
#1519=FACE_BOUND('',#1518,.T.);
#1520=CARTESIAN_POINT('',(39.,0.,32.6279999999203));
#1521=DIRECTION('',(0.,0.,-1.));
#1522=DIRECTION('',(0.,-1.,0.));
#1523=AXIS2_PLACEMENT_3D('',#1520,#1521,#1522);
#1524=CIRCLE('',#1523,2.4585);
#1525=CARTESIAN_POINT('',(39.,-2.45850000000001,32.6279999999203));
#1526=VERTEX_POINT('',#1525);
#1527=EDGE_CURVE('E980',#1526,#1526,#1524,.T.);
#1528=ORIENTED_EDGE('',*,*,#1527,.F.);
#1529=EDGE_LOOP('',(#1528));
#1530=FACE_BOUND('',#1529,.T.);
#1531=ADVANCED_FACE('F537',(#1519,#1530),#1516,.T.);
#1532=ORIENTED_EDGE('',*,*,#1527,.T.);
#1533=EDGE_LOOP('',(#1532));
#1534=FACE_BOUND('',#1533,.T.);
#1535=CARTESIAN_POINT('',(39.,0.,33.4584999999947));
#1536=DIRECTION('',(0.,0.,1.));
#1537=DIRECTION('',(1.,0.,0.));
#1538=AXIS2_PLACEMENT_3D('',#1535,#1536,#1537);
#1539=CIRCLE('',#1538,2.45849999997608);
#1540=CARTESIAN_POINT('',(41.4584999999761,0.,33.4584999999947));
#1541=VERTEX_POINT('',#1540);
#1542=EDGE_CURVE('E316',#1541,#1541,#1539,.T.);
#1543=ORIENTED_EDGE('',*,*,#1542,.T.);
#1544=EDGE_LOOP('',(#1543));
#1545=FACE_BOUND('',#1544,.T.);
#1546=ADVANCED_FACE('F291',(#1534,#1545),#401,.F.);
#1547=CARTESIAN_POINT('',(39.,0.,33.9999999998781));
#1548=DIRECTION('',(0.,0.,1.));
#1549=DIRECTION('',(0.,1.,0.));
#1550=AXIS2_PLACEMENT_3D('',#1547,#1548,#1549);
#1551=CONICAL_SURFACE('',#1550,2.99999999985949,0.785398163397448);
#1552=ORIENTED_EDGE('',*,*,#1507,.F.);
#1553=EDGE_LOOP('',(#1552));
#1554=FACE_BOUND('',#1553,.T.);
#1555=ORIENTED_EDGE('',*,*,#1542,.F.);
#1556=EDGE_LOOP('',(#1555));
#1557=FACE_BOUND('',#1556,.T.);
#1558=ADVANCED_FACE('F265',(#1554,#1557),#1551,.F.);
#1559=CLOSED_SHELL('',(#1491,#1511,#1531,#1546,#1558));
#1560=ORIENTED_CLOSED_SHELL('',*,#1559,.T.);
#1561=BREP_WITH_VOIDS('B1',#1463,(#1560));
#1562=ADVANCED_BREP_SHAPE_REPRESENTATION('',(#18,#1561),#14);
#1563=SHAPE_DEFINITION_REPRESENTATION(#9,#1562);
ENDSEC;
END-ISO-10303-21;
